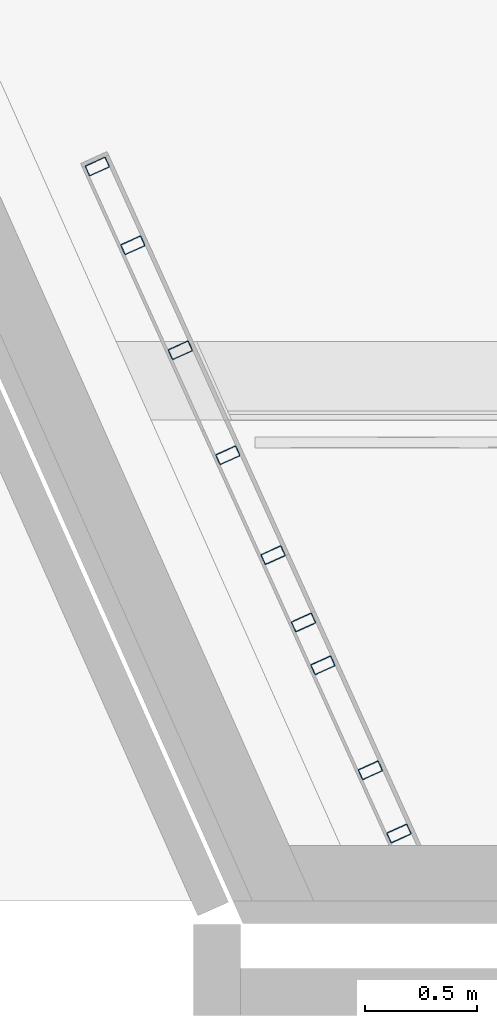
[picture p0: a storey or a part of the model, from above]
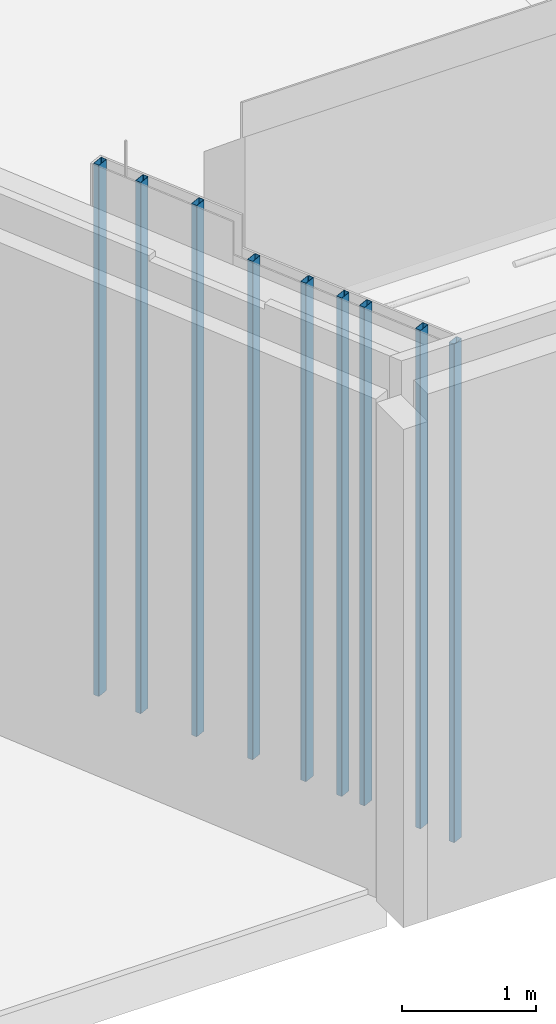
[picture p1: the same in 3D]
Properties of the parts of a building model (IFC2X3), part 1 of 2

# File
Description: ViewDefinition [CoordinationView_V2.0, QuantityTakeOffAddOnView]
File name: 10024017
Time: 2025-01-29T14:13:03+01:00
Written by: ODA SDAI 22.12
Made in: 23.0.11.19 - Exporter 23.0.11.19 - Alternate UI 23.0.11.19

# IfcProject, 10024017
LongName: CULTURA

# IfcSite, Default
RefLatitude: 52, 22, 22, 799999; RefLongitude: 4, 53, 41, 279999; RefElevation: 0 mm
Pset_ProductRequirements - Category: Project Information

# IfcBuilding
Pset_BuildingCommon - NumberOfStoreys: 4
Pset_ProductRequirements - Category: Project Information

# IfcBuildingStorey: Level:3.5mm bouwkundig (naam + hoogte) (4)
Pset_ProductRequirements - Category: Levels
Name | LongName | Elevation (mm) | Pset_AirSideSystemInformation, Name = Pset_ProductRequirements, Name
00 Begane grond | 00 Begane grond | 750 | 00 Begane grond o.k. vloer
01 1e verdieping | 01 1e verdieping | 4200 | 01 1e verdieping
02 2e verdieping | 02 2e verdieping | 9000 | 02 2e verdieping
03 3e verdieping | 03 3e verdieping | 12600 | 03 3e verdieping

# IfcSpace: BVO 2:5926632, 2
In: 00 Begane grond
Type - PredefinedType: USERDEFINED
LongName: BVO; InteriorOrExteriorSpace: INTERNAL; Group: BB. BVO
Pset_AirSideSystemInformation - Name: BVO
Pset_ProductRequirements - Name: BVO; Category: Areas
Pset_SpaceCommon - Reference: BVO 2; Category: Areas
BaseQuantities - NetFloorArea: 182.71 m2; Height: 3450 mm; GrossFloorArea: 182.71 m2; GrossVolume: 630.35 m3

# IfcSpace: BVO 4:6411099, 4
In: 01 1e verdieping
Type - PredefinedType: USERDEFINED
LongName: BVO; InteriorOrExteriorSpace: INTERNAL; Group: BB. BVO
Pset_AirSideSystemInformation - Name: BVO
Pset_ProductRequirements - Name: BVO; Category: Areas
Pset_SpaceCommon - Reference: BVO 4; Category: Areas
BaseQuantities - NetFloorArea: 341.625 m2; Height: 4800 mm; GrossFloorArea: 341.625 m2; GrossVolume: 1639.8 m3

# IfcSpace: BVO 5:6411158, 5
In: 02 2e verdieping
Type - PredefinedType: USERDEFINED
LongName: BVO; InteriorOrExteriorSpace: INTERNAL; Group: BB. BVO
Pset_AirSideSystemInformation - Name: BVO
Pset_ProductRequirements - Name: BVO; Category: Areas
Pset_SpaceCommon - Reference: BVO 5; Category: Areas
BaseQuantities - NetFloorArea: 78 m2; Height: 3600 mm; GrossFloorArea: 78 m2; GrossVolume: 280.8 m3

# IfcSpace: BVO 6:6413446, 6
In: 02 2e verdieping
Type - PredefinedType: USERDEFINED
LongName: BVO; InteriorOrExteriorSpace: INTERNAL; Group: BB. BVO
Pset_AirSideSystemInformation - Name: BVO
Pset_ProductRequirements - Name: BVO; Category: Areas
Pset_SpaceCommon - Reference: BVO 6; Category: Areas
BaseQuantities - NetFloorArea: 126 m2; Height: 3600 mm; GrossFloorArea: 126 m2; GrossVolume: 453.599 m3

# IfcSpace: Balkon 2.6:6415991, 2.6
In: 02 2e verdieping
LongName: Balkon; InteriorOrExteriorSpace: INTERNAL
Pset_AirSideSystemInformation - Name: Balkon
Pset_ProductRequirements - Name: Balkon; Category: Rooms
Pset_SpaceCommon - Reference: Balkon 2.6; Category: Rooms; FloorCovering: V2 Houten vloerafwerking
BaseQuantities - NetFloorArea: 319.853 m2; Height: 2438.4 mm; GrossFloorArea: 319.853 m2; GrossVolume: 779.93 m3

# IfcSpace: Multifunctionele zaal 1.4:6222861, 1.4
In: 01 1e verdieping
LongName: Multifunctionele zaal; InteriorOrExteriorSpace: INTERNAL
Pset_AirSideSystemInformation - Name: Multifunctionele zaal
Pset_ProductRequirements - Name: Multifunctionele zaal; Category: Rooms
Pset_SpaceCommon - Reference: Multifunctionele zaal 1.4; Category: Rooms; FloorCovering: V2 Houten vloerafwerking
BaseQuantities - NetFloorArea: 325.531 m2; Height: 2438.4 mm; GrossFloorArea: 325.531 m2; GrossVolume: 793.775 m3

# IfcSpace: Plateaulift 1.2:6222855, 1.2
In: 01 1e verdieping
LongName: Plateaulift; InteriorOrExteriorSpace: INTERNAL
Pset_AirSideSystemInformation - Name: Plateaulift
Pset_ProductRequirements - Name: Plateaulift; Category: Rooms
Pset_SpaceCommon - Reference: Plateaulift 1.2; Category: Rooms; FloorCovering: Geen vloerafwerking / vide; CeilingCovering: Geen plafondafwerking / vide
BaseQuantities - NetFloorArea: 1.27597 m2; Height: 2438.4 mm; GrossPerimeter: 4668.56 mm; GrossFloorArea: 1.27597 m2; GrossVolume: 3.11133 m3

# IfcSpace: Sluis 1.1:6222836, 1.1
In: 01 1e verdieping
LongName: Sluis; InteriorOrExteriorSpace: INTERNAL
Pset_AirSideSystemInformation - Name: Sluis
Pset_ProductRequirements - Name: Sluis; Category: Rooms
Pset_SpaceCommon - Reference: Sluis 1.1; Category: Rooms; FloorCovering: V1 Zachte vloerafwerking; CeilingCovering: P1 Systeemplafond
BaseQuantities - NetFloorArea: 3.37673 m2; Height: 2438.4 mm; GrossPerimeter: 7497.14 mm; GrossFloorArea: 3.37673 m2; GrossVolume: 8.23381 m3

# IfcSpace: Sluis 1.3:6222849, 1.3
In: 01 1e verdieping
LongName: Sluis; InteriorOrExteriorSpace: INTERNAL
Pset_AirSideSystemInformation - Name: Sluis
Pset_ProductRequirements - Name: Sluis; Category: Rooms
Pset_SpaceCommon - Reference: Sluis 1.3; Category: Rooms; FloorCovering: V1 Zachte vloerafwerking; CeilingCovering: P1 Systeemplafond
BaseQuantities - NetFloorArea: 3.03544 m2; Height: 2438.4 mm; GrossPerimeter: 8451.61 mm; GrossFloorArea: 3.03544 m2; GrossVolume: 7.40163 m3

# IfcSpace: Sluis 2.1:6356506, 2.1
In: 02 2e verdieping
LongName: Sluis; InteriorOrExteriorSpace: INTERNAL
Pset_AirSideSystemInformation - Name: Sluis
Pset_ProductRequirements - Name: Sluis; Category: Rooms
Pset_SpaceCommon - Reference: Sluis 2.1; Category: Rooms; FloorCovering: V1 Zachte vloerafwerking; CeilingCovering: P1 Systeemplafond
BaseQuantities - NetFloorArea: 3.37673 m2; Height: 2438.4 mm; GrossPerimeter: 7497.14 mm; GrossFloorArea: 3.37673 m2; GrossVolume: 8.23381 m3

# IfcSpace: Sluis 2.3:6356499, 2.3
In: 02 2e verdieping
LongName: Sluis; InteriorOrExteriorSpace: INTERNAL
Pset_AirSideSystemInformation - Name: Sluis
Pset_ProductRequirements - Name: Sluis; Category: Rooms
Pset_SpaceCommon - Reference: Sluis 2.3; Category: Rooms; FloorCovering: V1 Zachte vloerafwerking; CeilingCovering: P1 Systeemplafond
BaseQuantities - NetFloorArea: 3.0787 m2; Height: 2438.4 mm; GrossPerimeter: 8620.86 mm; GrossFloorArea: 3.0787 m2; GrossVolume: 7.5071 m3

# IfcSpace: Techniek 2.2:6356521, 2.2
In: 02 2e verdieping
LongName: Techniek; InteriorOrExteriorSpace: INTERNAL
Pset_AirSideSystemInformation - Name: Techniek
Pset_ProductRequirements - Name: Techniek; Category: Rooms
Pset_SpaceCommon - Reference: Techniek 2.2; Category: Rooms; FloorCovering: V3 Elastische vloerafwerking; CeilingCovering: P3 Sauswerk
BaseQuantities - NetFloorArea: 4.30041 m2; Height: 2438.4 mm; GrossFloorArea: 4.30041 m2; GrossVolume: 10.4861 m3

# IfcSpace: Theatertechniek 3.13:6422108, 3.13
In: 03 3e verdieping
LongName: Theatertechniek; InteriorOrExteriorSpace: INTERNAL
Pset_AirSideSystemInformation - Name: Theatertechniek
Pset_ProductRequirements - Name: Theatertechniek; Category: Rooms
Pset_SpaceCommon - Reference: Theatertechniek 3.13; Category: Rooms; CeilingCovering: P4 Systeemplafond
BaseQuantities - NetFloorArea: 102.625 m2; Height: 2438.4 mm; GrossFloorArea: 102.625 m2; GrossVolume: 250.241 m3

# IfcBuildingElementProxy: $9_APX_brandslanghaspel 30m - inbouw:$9_APX_brandslanghaspel 30m - inbouw (2)
In: 1.4
Type - Material: <Unnamed>
Type - Pset_ProductRequirements - Category: Generic Models
Pset_BuildingElementProxyCommon - Reference: $9_APX_brandslanghaspel 30m - inbouw:$9_APX_brandslanghaspel 30m - inbouw; sets with these values: 2
Name ($9_APX_brandslanghaspel 30m - inbouw:$9_APX_brandslanghaspel 30m - inbouw:...)
6395932
6396388

# IfcBuildingElementProxy: NLRS_53_GM_brandslanghaspel opbouw_ags:20 meter (13)
Type - Classification: 53.0 water; algemeen (Uniformat); Material: <Unnamed>
Type - Pset_ProductRequirements - Category: Generic Models
Pset_BuildingElementProxyCommon - Reference: NLRS_53_GM_brandslanghaspel opbouw_ags:20 meter; sets with these values: 2
Name (NLRS_53_GM_brandslanghaspel opbouw_ags:20 meter:...) | In
6379921 | 01 1e verdieping
6380212 | 2.1
6380439 | 02 2e verdieping
6380646 | 01 1e verdieping
6380734 | 02 2e verdieping
6390924 | 01 1e verdieping
6390974 | 02 2e verdieping
6391039 | 03 3e verdieping
6391112 | 03 3e verdieping
6391162 | 3.13
6391226 | 03 3e verdieping
6423973 | 01 1e verdieping
6449209 | 2.3

# IfcBuildingElementProxy: Storax-kooiladder-DLL-VM-K:GL-VM-K, Storax-kooiladder-DLL-VM-K:GL-VM-K:6451924
In: 02 2e verdieping
Type - Material: bcb_aluminium (43)
Type - Pset_ManufacturerTypeInformation - Manufacturer: Storax
Type - Pset_ProductRequirements - Category: Generic Models
Pset_BuildingElementProxyCommon - Reference: Storax-kooiladder-DLL-VM-K:GL-VM-K; sets with these values: 2
Pset_ProvisionForVoid - Width: 8 mm; Height: 70 mm; Depth: 70 mm

# IfcColumn: Kokerprofielen_ITX(c):K100/50/2.5 (39)
Type - PredefinedType: COLUMN; Classification: (28.a) (Uniformat); Material: Metal - Steel - 345 MPa
Type - Pset_ColumnCommon - IsExternal: no; LoadBearing: yes
Type - Pset_ProductRequirements - Category: Structural Columns
BaseQuantities - CrossSectionArea: 0.00070889 m2
Pset_ColumnCommon - Reference: Kokerprofielen_ITX(c):K100/50/2.5
Pset_QuantityTakeOff - Reference: Kokerprofielen_ITX(c):K100/50/2.5; sets with these values: 2
Name (Kokerprofielen_ITX(c):K100/50/2.5:...) | In | Length (mm) | OuterSurfaceArea (m2) | GrossVolume (m3) | NetVolume (m3)
6153715 | 01 1e verdieping | 4550 | 2.58041 | 0.00322545 | 0.00322534
6155034 | 01 1e verdieping | 4550 | 2.58041 | 0.00322545
6155050 | 01 1e verdieping | 4550 | 2.58041 | 0.00322545
6155062 | 01 1e verdieping | 4550 | 2.58041 | 0.00322545
6155076 | 01 1e verdieping | 4550 | 2.58041 | 0.00322545
6155090 | 01 1e verdieping | 4550 | 2.58041 | 0.00322545
6164741 | 01 1e verdieping | 4850 | 2.75055 | 0.00343811 | 0.00343799
6164741 | 02 2e verdieping | 3500 | 1.98493 | 0.00248111 | 0.00248103
6164755 | 01 1e verdieping | 4550 | 2.58041 | 0.00322545 | 0.00322534
6164765 | 01 1e verdieping | 4550 | 2.58041 | 0.00322545
6164779 | 01 1e verdieping | 4550 | 2.58041 | 0.00322545
6164791 | 01 1e verdieping | 4550 | 2.58041 | 0.00322545
6164801 | 01 1e verdieping | 4550 | 2.58041 | 0.00322545
6164815 | 01 1e verdieping | 4550 | 2.58041 | 0.00322545
6287158 | 02 2e verdieping | 3550 | 2.01329 | 0.00251656 | 0.00251647
6287159 | 02 2e verdieping | 3550 | 2.01329 | 0.00251656
6287160 | 02 2e verdieping | 3550 | 2.01329 | 0.00251656
6287161 | 02 2e verdieping | 3550 | 2.01329 | 0.00251656
6287162 | 02 2e verdieping | 1300 | 0.737261 | 0.000921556 | 0.000921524
6287163 | 02 2e verdieping | 1300 | 0.737261 | 0.000921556
6294994 | 02 2e verdieping | 1300 | 0.737261 | 0.000921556 | 0.000921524
6294995 | 02 2e verdieping | 1300 | 0.737261 | 0.000921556
6294996 | 02 2e verdieping | 1300 | 0.737261 | 0.000921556
6294997 | 02 2e verdieping | 3550 | 2.01329 | 0.00251656 | 0.00251647
6294998 | 02 2e verdieping | 3550 | 2.01329 | 0.00251656
6294999 | 02 2e verdieping | 3550 | 2.01329 | 0.00251656
6295000 | 02 2e verdieping | 3550 | 2.01329 | 0.00251656
6331567 | 01 1e verdieping | 4850 | 2.75055 | 0.00343811 | 0.00343799
6331567 | 02 2e verdieping | 3500 | 1.98493 | 0.00248111 | 0.00248103
6331577 | 01 1e verdieping | 4850 | 2.75055 | 0.00343811 | 0.00343799
6331577 | 02 2e verdieping | 3500 | 1.98493 | 0.00248111 | 0.00248103
6331587 | 01 1e verdieping | 4850 | 2.75055 | 0.00343811 | 0.00343799
6331587 | 02 2e verdieping | 3500 | 1.98493 | 0.00248111 | 0.00248103
6338354 | 01 1e verdieping | 4850 | 2.75055 | 0.00343811 | 0.00343799
6338354 | 02 2e verdieping | 3500 | 1.98493 | 0.00248111 | 0.00248103
6338366 | 01 1e verdieping | 4850 | 2.75055 | 0.00343811 | 0.00343799
6338366 | 02 2e verdieping | 3500 | 1.98493 | 0.00248111 | 0.00248103
6338687 | 01 1e verdieping | 4850 | 2.75055 | 0.00343811 | 0.00343799
6338687 | 02 2e verdieping | 3500 | 1.98493 | 0.00248111 | 0.00248103

# IfcCovering: Compound Ceiling:NLRS_45_CEI_ontwerpplafond 100mm_ags (3)
Type - PredefinedType: CEILING
Type - Pset_CoveringCommon - TotalThickness: 100 mm
Type - Pset_ElementShading - Roughness: 304.8 mm
Type - Pset_ProductRequirements - Category: Ceilings
Classification: 45.11 plafondafwerkingen; verlaagd, verlaagde plafonds (Uniformat); Material: NLRS_ontwerpmateriaal grijs 100 mm
Pset_CoveringCommon - Reference: Compound Ceiling:NLRS_45_CEI_ontwerpplafond 100mm_ags; sets with these values: 2
Name (Compound Ceiling:NLRS_45_CEI_ontwerpplafond 100mm_ags:...) | In | GrossCeilingArea (m2)
6311351 | 3.13 | 341.626
6344896 | 01 1e verdieping | 63.2539
6346580 | 01 1e verdieping | 31.6356

# IfcCurtainWall: Curtain Wall:NLRS_32_CWA_houten binnenkozijnen ts90_ags (24)
Type - Pset_CurtainWallCommon - IsExternal: no
Type - Pset_ProductRequirements - Category: Walls
Classification: 32.40 binnenwandopeningen; gevuld met puien, algemeen (verzamelniveau) (Uniformat)
Pset_CurtainWallCommon - Reference: Curtain Wall:NLRS_32_CWA_houten binnenkozijnen ts90_ags
Pset_QuantityTakeOff - Reference: Curtain Wall:NLRS_32_CWA_houten binnenkozijnen ts90_ags
Name (Curtain Wall:NLRS_32_CWA_houten binnenkozijnen ts90_ags:...) | In | Pset_ConcreteElementGeneral, FireRating = Pset_CurtainWallCommon, FireRating
6147847 | 01 1e verdieping | 30
6148407 | 01 1e verdieping | 30
6149483 | 01 1e verdieping | 30
6149900 | 01 1e verdieping | 60
6151805 | 01 1e verdieping | 30
6152954 | 01 1e verdieping | 30
6158346 | 01 1e verdieping | 30
6224134 | 01 1e verdieping | 30
6225151 | 02 2e verdieping | 30
6225855 | 02 2e verdieping | 30
6225909 | 02 2e verdieping | 30
6228164 | 02 2e verdieping | 60
6245156 | 01 1e verdieping | 0
6264043 | 02 2e verdieping | 30
6282615 | 01 1e verdieping | 0
6292872 | 02 2e verdieping | 30
6339797 | 01 1e verdieping | 0
6364564 | 01 1e verdieping | 30
6365035 | 02 2e verdieping | 30
6366062 | 02 2e verdieping | 30
6383929 | 03 3e verdieping | 60
6423692 | 02 2e verdieping | 30
6424522 | 01 1e verdieping | 0
6452049 | 02 2e verdieping

# IfcDoor: NLRS_31_DO_houten deur kiep boven_ags:deur dicht, NLRS_31_DO_houten deur kiep boven_ags:deur dicht:6260981
In: 01 1e verdieping
Type - ParameterTakesPrecedence: no; Sizeable: no; Classification: 31.31 buitenwandopeningen; gevuld met deuren, draaideuren (Uniformat); Material: NLRS_a_clashvolume, <Unnamed>
Type - Pset_DoorCommon - IsExternal: yes
Type - Pset_ProductRequirements - Category: Doors
OverallHeight: 613 mm; OverallWidth: 1731 mm; Classification: 32.40 binnenwandopeningen; gevuld met puien, algemeen (verzamelniveau) (Uniformat)
Pset_DoorCommon - Reference: NLRS_31_DO_houten deur kiep boven_ags:deur dicht
Pset_QuantityTakeOff - Reference: NLRS_31_DO_houten deur kiep boven_ags:deur dicht
BaseQuantities - Height: 613 mm; Width: 1731 mm; Area: 1.0611 m2

# IfcDoor: NLRS_31_DO_houten deur_ags:deur dicht (30)
Type - ParameterTakesPrecedence: no; Sizeable: no; Classification: 31.31 buitenwandopeningen; gevuld met deuren, draaideuren (Uniformat); Material: NLRS_a_clashvolume, <Unnamed>
Type - Pset_DoorCommon - IsExternal: yes
Type - Pset_ProductRequirements - Category: Doors
Classification: 32.40 binnenwandopeningen; gevuld met puien, algemeen (verzamelniveau) (Uniformat)
Pset_DoorCommon - Reference: NLRS_31_DO_houten deur_ags:deur dicht
Pset_QuantityTakeOff - Reference: NLRS_31_DO_houten deur_ags:deur dicht
Name (NLRS_31_DO_houten deur_ags:deur dicht:...) | In | OverallHeight (mm) = Height (mm) | OverallWidth (mm) = Width (mm) | Area (m2)
6147848 | 01 1e verdieping | 2103 | 1013 | 2.13034
6147853 | 01 1e verdieping | 2103 | 352.761 | 0.741856
6148408 | 01 1e verdieping | 2103 | 1086 | 2.28386
6149484 | 01 1e verdieping | 2103 | 906 | 1.90532
6149901 | 01 1e verdieping | 2103 | 886 | 1.86326
6151806 | 01 1e verdieping | 2320 | 865.5 | 2.00796
6151811 | 01 1e verdieping | 2320 | 865.5 | 2.00796
6152955 | 01 1e verdieping | 2103 | 906 | 1.90532
6158347 | 01 1e verdieping | 2103 | 931 | 1.95789
6224135 | 01 1e verdieping | 2103 | 807.995 | 1.69921
6224140 | 01 1e verdieping | 2103 | 808 | 1.69922
6225152 | 02 2e verdieping | 2103 | 918 | 1.93055
6225157 | 02 2e verdieping | 2103 | 447.761 | 0.941641
6225856 | 02 2e verdieping | 2103 | 906 | 1.90532
6225910 | 02 2e verdieping | 2103 | 931 | 1.95789
6228165 | 02 2e verdieping | 2103 | 886 | 1.86326
6264044 | 02 2e verdieping | 2103 | 886 | 1.86326
6282616 | 01 1e verdieping | 2103 | 800.323 | 1.68308
6282621 | 01 1e verdieping | 2103 | 800.323 | 1.68308
6292873 | 02 2e verdieping | 2103 | 886 | 1.86326
6339798 | 01 1e verdieping | 2103 | 800.323 | 1.68308
6339803 | 01 1e verdieping | 2103 | 800.323 | 1.68308
6365036 | 02 2e verdieping | 2103 | 598.65 | 1.25896
6365041 | 02 2e verdieping | 2103 | 1013 | 2.13034
6366063 | 02 2e verdieping | 2103 | 807.995 | 1.69921
6366068 | 02 2e verdieping | 2103 | 808 | 1.69922
6383930 | 03 3e verdieping | 2103 | 806 | 1.69502
6423693 | 02 2e verdieping | 2103 | 906 | 1.90532
6424523 | 01 1e verdieping | 2103 | 933 | 1.9621
6424779 | 01 1e verdieping | 2103 | 783 | 1.64665

# IfcDoor: NLRS_31_DO_houten deur_ags:deur met maximaal glas (2)
In: 01 1e verdieping
Type - ParameterTakesPrecedence: no; Sizeable: no; Classification: 31.31 buitenwandopeningen; gevuld met deuren, draaideuren (Uniformat); Material: NLRS_a_clashvolume, Glas, <Unnamed>
Type - Pset_DoorCommon - IsExternal: yes
Type - Pset_ProductRequirements - Category: Doors
OverallHeight: 2103 mm; Classification: 32.40 binnenwandopeningen; gevuld met puien, algemeen (verzamelniveau) (Uniformat)
Pset_DoorCommon - Reference: NLRS_31_DO_houten deur_ags:deur met maximaal glas
Pset_QuantityTakeOff - Reference: NLRS_31_DO_houten deur_ags:deur met maximaal glas
BaseQuantities - Height: 2103 mm
Name (NLRS_31_DO_houten deur_ags:deur met maximaal glas:...) | OverallWidth (mm) = Width (mm) | Area (m2)
6364565 | 703 | 1.47841
6364570 | 1013 | 2.13034

# IfcFurnishingElement: Chair-Hussey-Quattro-Art_Series-Linear-3D-Metric:Chair-Hussey-Quattro-Art_Series-Linear-3D-Metric, Chair-Hussey-Quattro-Art_Series-Linear-3D-Metric:Chair-Hussey-Quattro-Art_Series-Linear-3D-Metric:6213181
In: 01 1e verdieping
Type - Classification: E2010500 (Uniformat); Material: Hussey - Fabric - Culp Contract - Dillon - Cordovan (2), Hussey - Wood - Grasswood - Natural Finish (6), Hussey - Paint - Titanium (26), <Unnamed> (2)
Type - Pset_FurnitureTypeCommon - Description: Quattro Art Series
Type - Pset_ManufacturerTypeInformation - Manufacturer: Hussey Seating Company
Type - Pset_ProductRequirements - Category: Furniture
Pset_QuantityTakeOff - Reference: Chair-Hussey-Quattro-Art_Series-Linear-3D-Metric:Chair-Hussey-Quattro-Art_Series-Linear-3D-Metric

# IfcFurnishingElement: Chair-Hussey-Quattro-Classic-3D:Chair-Hussey-Quattro-Classic-3D, Chair-Hussey-Quattro-Classic-3D:Chair-Hussey-Quattro-Classic-3D:6213133
In: 01 1e verdieping
Type - Classification: E2010500 (Uniformat); Material: <Unnamed> (27), Hussey - Seat Pad - Generic (2)
Type - Pset_FurnitureTypeCommon - Description: Quattro Collection
Type - Pset_ManufacturerTypeInformation - Manufacturer: Hussey Seating Company
Type - Pset_ProductRequirements - Category: Furniture
Pset_QuantityTakeOff - Reference: Chair-Hussey-Quattro-Classic-3D:Chair-Hussey-Quattro-Classic-3D

# IfcMember: Rectangular Mullion:NLRS_32_CWM_hout 114x67_ags (85)
Type - PredefinedType: MULLION; Material: <Unnamed>
Type - Pset_MemberCommon - IsExternal: no
Type - Pset_ProductRequirements - Category: Curtain Wall Mullions
Classification: 32.40 binnenwandopeningen; gevuld met puien, algemeen (verzamelniveau) (Uniformat)
Pset_MemberCommon - Reference: Rectangular Mullion:NLRS_32_CWM_hout 114x67_ags
Pset_QuantityTakeOff - Reference: Rectangular Mullion:NLRS_32_CWM_hout 114x67_ags
Name (Rectangular Mullion:NLRS_32_CWM_hout 114x67_ags:...) | In | Span (mm) = Length (mm) | CrossSectionArea (m2) | NetVolume (m3) | NetSurfaceArea (m2)
6147849 | 01 1e verdieping | 419.761 | 0.0836147 | 0.00320613 | 0.159591
6147850 | 01 1e verdieping | 2103 | 0.388281 | 0.0160627 | 0.776562
6147851 | 01 1e verdieping | 2103 | 0.388281 | 0.0160627 | 0.776562
6147854 | 01 1e verdieping | 1080 | 0.203118 | 0.00824904 | 0.398598
6148410 | 01 1e verdieping | 1086 | 0.204204 | 0.00829487 | 0.408408
6148412 | 01 1e verdieping | 2170 | 0.400408 | 0.0165745 | 0.800816
6148413 | 01 1e verdieping | 2170 | 0.400408 | 0.0165745 | 0.800816
6149485 | 01 1e verdieping | 906 | 0.171624 | 0.00692003 | 0.343248
6149486 | 01 1e verdieping | 2170 | 0.400408 | 0.0165745 | 0.800816
6149487 | 01 1e verdieping | 2170 | 0.400408 | 0.0165745 | 0.800816
6149902 | 01 1e verdieping | 886 | 0.168004 | 0.00676727 | 0.336008
6149903 | 01 1e verdieping | 2170 | 0.400408 | 0.0165745 | 0.800816
6149904 | 01 1e verdieping | 2170 | 0.400408 | 0.0165745 | 0.800816
6151807 | 01 1e verdieping | 865.5 | 0.164294 | 0.00661069 | 0.320949
6151808 | 01 1e verdieping | 2320 | 0.427558 | 0.0177202 | 0.847478
6151809 | 01 1e verdieping | 613 | 0.118591 | 0.00468209 | 0.229544
6151812 | 01 1e verdieping | 932.5 | 0.17642 | 0.00712243 | 0.345203
6260990 | 01 1e verdieping | 680 | 0.130718 | 0.00519384 | 0.253798
6260991 | 01 1e verdieping | 2320 | 0.427558 | 0.0177202 | 0.847478
6152956 | 01 1e verdieping | 906 | 0.171624 | 0.00692003 | 0.343248
6152957 | 01 1e verdieping | 2170 | 0.400408 | 0.0165745 | 0.800816
6152958 | 01 1e verdieping | 2170 | 0.400408 | 0.0165745 | 0.800816
6158348 | 01 1e verdieping | 931 | 0.176149 | 0.00711098 | 0.352298
6158349 | 01 1e verdieping | 2170 | 0.400408 | 0.0165745 | 0.800816
6158350 | 01 1e verdieping | 2170 | 0.400408 | 0.0165745 | 0.800816
6224136 | 01 1e verdieping | 875 | 0.166013 | 0.00668325 | 0.324388
6224137 | 01 1e verdieping | 2103 | 0.388281 | 0.0160627 | 0.776562
6224138 | 01 1e verdieping | 2103 | 0.388281 | 0.0160627 | 0.776562
6224141 | 01 1e verdieping | 874.995 | 0.166012 | 0.00668321 | 0.324386
6225153 | 02 2e verdieping | 514.761 | 0.10081 | 0.00393174 | 0.193981
6225154 | 02 2e verdieping | 2103 | 0.388281 | 0.0160627 | 0.776562
6225155 | 02 2e verdieping | 2103 | 0.388281 | 0.0160627 | 0.776562
6225158 | 02 2e verdieping | 985 | 0.185923 | 0.00752343 | 0.364208
6225857 | 02 2e verdieping | 906 | 0.171624 | 0.00692003 | 0.343248
6225858 | 02 2e verdieping | 2170 | 0.400408 | 0.0165745 | 0.800816
6225859 | 02 2e verdieping | 2170 | 0.400408 | 0.0165745 | 0.800816
6225911 | 02 2e verdieping | 931 | 0.176149 | 0.00711098 | 0.352298
6225912 | 02 2e verdieping | 2170 | 0.400408 | 0.0165745 | 0.800816
6225913 | 02 2e verdieping | 2170 | 0.400408 | 0.0165745 | 0.800816
6228166 | 02 2e verdieping | 886 | 0.168004 | 0.00676727 | 0.336008
6228167 | 02 2e verdieping | 2170 | 0.400408 | 0.0165745 | 0.800816
6228168 | 02 2e verdieping | 2170 | 0.400408 | 0.0165745 | 0.800816
6245158 | 01 1e verdieping | 886 | 0.168004 | 0.00676727 | 0.336008
6245159 | 01 1e verdieping | 2170 | 0.400408 | 0.0165745 | 0.800816
6245160 | 01 1e verdieping | 2170 | 0.400408 | 0.0165745 | 0.800816
6264045 | 02 2e verdieping | 886 | 0.168004 | 0.00676727 | 0.336008
6264046 | 02 2e verdieping | 2170 | 0.400408 | 0.0165745 | 0.800816
6264047 | 02 2e verdieping | 2170 | 0.400408 | 0.0165745 | 0.800816
6282617 | 01 1e verdieping | 867.323 | 0.164623 | 0.00662461 | 0.321609
6282618 | 01 1e verdieping | 2103 | 0.388281 | 0.0160627 | 0.776562
6282619 | 01 1e verdieping | 2103 | 0.388281 | 0.0160627 | 0.776562
6282622 | 01 1e verdieping | 867.323 | 0.164623 | 0.00662461 | 0.321609
6292874 | 02 2e verdieping | 886 | 0.168004 | 0.00676727 | 0.336008
6292875 | 02 2e verdieping | 2170 | 0.400408 | 0.0165745 | 0.800816
6292876 | 02 2e verdieping | 2170 | 0.400408 | 0.0165745 | 0.800816
6339799 | 01 1e verdieping | 867.323 | 0.164623 | 0.00662461 | 0.321609
6339800 | 01 1e verdieping | 2103 | 0.388281 | 0.0160627 | 0.776562
6339801 | 01 1e verdieping | 2103 | 0.388281 | 0.0160627 | 0.776562
6339804 | 01 1e verdieping | 867.323 | 0.164623 | 0.00662461 | 0.321609
6364566 | 01 1e verdieping | 1080 | 0.203118 | 0.00824904 | 0.398598
6364567 | 01 1e verdieping | 2103 | 0.388281 | 0.0160627 | 0.776562
6364568 | 01 1e verdieping | 2103 | 0.388281 | 0.0160627 | 0.776562
6364571 | 01 1e verdieping | 770 | 0.147008 | 0.00588126 | 0.286378
6365037 | 02 2e verdieping | 1080 | 0.203118 | 0.00824904 | 0.398598
6365038 | 02 2e verdieping | 2103 | 0.388281 | 0.0160627 | 0.776562
6365039 | 02 2e verdieping | 2103 | 0.388281 | 0.0160627 | 0.776562
6365042 | 02 2e verdieping | 665.65 | 0.128121 | 0.00508423 | 0.248603
6366064 | 02 2e verdieping | 875 | 0.166013 | 0.00668325 | 0.324388
6366065 | 02 2e verdieping | 2103 | 0.388281 | 0.0160627 | 0.776562
6366066 | 02 2e verdieping | 2103 | 0.388281 | 0.0160627 | 0.776562
6366069 | 02 2e verdieping | 874.995 | 0.166012 | 0.00668321 | 0.324386
6383931 | 03 3e verdieping | 806 | 0.153524 | 0.00615623 | 0.307048
6383932 | 03 3e verdieping | 2170 | 0.400408 | 0.0165745 | 0.800816
6383933 | 03 3e verdieping | 2170 | 0.400408 | 0.0165745 | 0.800816
6423694 | 02 2e verdieping | 906 | 0.171624 | 0.00692003 | 0.343248
6423695 | 02 2e verdieping | 2170 | 0.400408 | 0.0165745 | 0.800816
6423696 | 02 2e verdieping | 2170 | 0.400408 | 0.0165745 | 0.800816
6424524 | 01 1e verdieping | 850 | 0.161488 | 0.0064923 | 0.315338
6424525 | 01 1e verdieping | 2103 | 0.388281 | 0.0160627 | 0.776562
6424526 | 01 1e verdieping | 2103 | 0.388281 | 0.0160627 | 0.776562
6424785 | 01 1e verdieping | 1000 | 0.188638 | 0.007638 | 0.369638
6452091 | 02 2e verdieping | 416 | 0.082934 | 0.00317741 | 0.165868
6452092 | 02 2e verdieping | 416 | 0.082934 | 0.00317741 | 0.165868
6452093 | 02 2e verdieping | 550 | 0.107188 | 0.0042009 | 0.214376
6452094 | 02 2e verdieping | 550 | 0.107188 | 0.0042009 | 0.214376

# IfcOpeningElement: Opening (65)
Pset_OpeningElementCommon - sets with these values: 2
Name | In | Classification | Reference | Category | Depth (mm) | Height (mm) | Width (mm)
Basic Wall:NLRS_22_WA_kalkzandsteen 150mm_ags:6136175 | 01 1e verdieping | 22.11 binnenwanden; niet constructief, massieve wanden (Uniformat) | Constructie voids:Constructie voids | Walls
Basic Wall:NLRS_21_WA_beton 250mm_ags:6137919 | 01 1e verdieping | 21.11 buitenwanden; niet constructief, massieve wanden (Uniformat) | Basic Wall:NLRS_21_WA_beton 250mm_ags | Walls: Rectangular Straight Wall Opening | 250 | 1040 | 2220
Basic Wall:NLRS_21_WA_beton 250mm_ags:6138007 | 01 1e verdieping | 21.11 buitenwanden; niet constructief, massieve wanden (Uniformat) | Basic Wall:NLRS_21_WA_beton 250mm_ags | Walls: Rectangular Straight Wall Opening | 250 | 1840 | 2220
Basic Wall:NLRS_21_WA_beton 250mm_ags:6138079 | 01 1e verdieping | 21.11 buitenwanden; niet constructief, massieve wanden (Uniformat) | Basic Wall:NLRS_21_WA_beton 250mm_ags | Walls: Rectangular Straight Wall Opening | 250 | 1865 | 3050
Basic Wall:NLRS_22_WA_kalkzandsteen 150mm_ags:6138243 | 01 1e verdieping | 22.11 binnenwanden; niet constructief, massieve wanden (Uniformat) | Basic Wall:NLRS_22_WA_kalkzandsteen 150mm_ags | Walls: Rectangular Straight Wall Opening | 150 | 1040 | 2220
Basic Wall:NLRS_22_WA_kalkzandsteen 150mm_ags:6138328 | 01 1e verdieping | 22.11 binnenwanden; niet constructief, massieve wanden (Uniformat) | Basic Wall:NLRS_22_WA_kalkzandsteen 150mm_ags | Walls: Rectangular Straight Wall Opening | 150 | 1840 | 2170
Basic Wall:NLRS_22_WA_kalkzandsteen 150mm_ags:6138469 | 01 1e verdieping | 22.11 binnenwanden; niet constructief, massieve wanden (Uniformat) | Basic Wall:NLRS_22_WA_kalkzandsteen 150mm_ags | Walls: Rectangular Straight Wall Opening | 150 | 1865 | 3050
Basic Wall:NLRS_22_WA_kalkzandsteen 150mm_ags:6138469 | 01 1e verdieping | 22.11 binnenwanden; niet constructief, massieve wanden (Uniformat) | Curtain Wall:NLRS_32_CWA_houten binnenkozijnen ts90_ags | Walls | 454.8 | 3000 | 1865
2 x Basic Wall:NLRS_22_WA_kalkzandsteen 150mm_ags:6138796 | 01 1e verdieping | 22.11 binnenwanden; niet constructief, massieve wanden (Uniformat) | Basic Wall:NLRS_22_WA_kalkzandsteen 150mm_ags | Walls: Rectangular Straight Wall Opening | 150 | 1499.76 | 2220
Basic Wall:NLRS_22_WA_kalkzandsteen 150mm_ags:6138796 | 01 1e verdieping | 22.11 binnenwanden; niet constructief, massieve wanden (Uniformat) | Curtain Wall:NLRS_32_CWA_houten binnenkozijnen ts90_ags | Walls | 454.8 | 1499.76 | 2170
Basic Wall:NLRS_22_WA_kalkzandsteen 150mm_ags:6138796 | 01 1e verdieping | 22.11 binnenwanden; niet constructief, massieve wanden (Uniformat) | Constructie voids:Constructie voids | Walls
Basic Wall:NLRS_21_WA_beton 250mm_ags:6140967 | 01 1e verdieping | 21.11 buitenwanden; niet constructief, massieve wanden (Uniformat) | Basic Wall:NLRS_21_WA_beton 250mm_ags | Walls: Rectangular Straight Wall Opening | 250 | 1065 | 2220
2 x Basic Wall:NLRS_22_WA_kalkzandsteen 150mm_ags:6142320 | 01 1e verdieping | 22.11 binnenwanden; niet constructief, massieve wanden (Uniformat) | Basic Wall:NLRS_22_WA_kalkzandsteen 150mm_ags | Walls: Rectangular Straight Wall Opening | 150 | 1020 | 2220
Basic Wall:NLRS_22_WA_kalkzandsteen 150mm_ags:6142320 | 01 1e verdieping | 22.11 binnenwanden; niet constructief, massieve wanden (Uniformat) | Curtain Wall:NLRS_32_CWA_houten binnenkozijnen ts90_ags | Walls | 454.8 | 1020 | 2170
2 x Basic Wall:NLRS_22_WA_kalkzandsteen 150mm_ags:6142474 | 01 1e verdieping | 22.11 binnenwanden; niet constructief, massieve wanden (Uniformat) | Basic Wall:NLRS_22_WA_kalkzandsteen 150mm_ags | Walls: Rectangular Straight Wall Opening | 150 | 1065 | 2220
Basic Wall:NLRS_21_WA_beton 250mm_ags:6143536 | 02 2e verdieping | 21.11 buitenwanden; niet constructief, massieve wanden (Uniformat) | Basic Wall:NLRS_21_WA_beton 250mm_ags | Walls: Rectangular Straight Wall Opening | 250 | 940 | 2220
Basic Wall:NLRS_21_WA_beton 250mm_ags:6143536 | 03 3e verdieping | 21.11 buitenwanden; niet constructief, massieve wanden (Uniformat) | Basic Wall:NLRS_21_WA_beton 250mm_ags | Walls: Rectangular Straight Wall Opening | 250 | 940 | 2220
Basic Wall:NLRS_21_WA_beton 250mm_ags:6143537 | 02 2e verdieping | 21.11 buitenwanden; niet constructief, massieve wanden (Uniformat) | Basic Wall:NLRS_21_WA_beton 250mm_ags | Walls: Rectangular Straight Wall Opening | 250 | 1030 | 2220
Basic Wall:NLRS_21_WA_beton 250mm_ags:6143539 | 02 2e verdieping | 21.11 buitenwanden; niet constructief, massieve wanden (Uniformat) | Basic Wall:NLRS_21_WA_beton 250mm_ags | Walls: Rectangular Straight Wall Opening | 250 | 1065 | 2220
Basic Wall:NLRS_21_WA_beton 250mm_ags:6143544 | 02 2e verdieping | 21.11 buitenwanden; niet constructief, massieve wanden (Uniformat) | Basic Wall:NLRS_21_WA_beton 250mm_ags | Walls: Rectangular Straight Wall Opening | 250 | 1065 | 2220
Basic Wall:NLRS_22_WA_kalkzandsteen 150mm_ags:6144485 | 02 2e verdieping | 22.11 binnenwanden; niet constructief, massieve wanden (Uniformat) | Basic Wall:NLRS_22_WA_kalkzandsteen 150mm_ags | Walls: Rectangular Straight Wall Opening | 150 | 940 | 2220
Basic Wall:NLRS_22_WA_kalkzandsteen 150mm_ags:6144485 | 03 3e verdieping | 22.11 binnenwanden; niet constructief, massieve wanden (Uniformat) | Basic Wall:NLRS_22_WA_kalkzandsteen 150mm_ags | Walls: Rectangular Straight Wall Opening | 150 | 940 | 2220
Basic Wall:NLRS_22_WA_kalkzandsteen 150mm_ags:6144485 | 03 3e verdieping | 22.11 binnenwanden; niet constructief, massieve wanden (Uniformat) | Curtain Wall:NLRS_32_CWA_houten binnenkozijnen ts90_ags | Walls | 454.8 | 940 | 2170
Basic Wall:NLRS_22_WA_kalkzandsteen 150mm_ags:6144486 | 02 2e verdieping | 22.11 binnenwanden; niet constructief, massieve wanden (Uniformat) | Basic Wall:NLRS_22_WA_kalkzandsteen 150mm_ags | Walls: Rectangular Straight Wall Opening | 150 | 1030 | 2220
Basic Wall:NLRS_22_WA_kalkzandsteen 150mm_ags:6144489 | 02 2e verdieping | 22.11 binnenwanden; niet constructief, massieve wanden (Uniformat) | Basic Wall:NLRS_22_WA_kalkzandsteen 150mm_ags | Walls: Rectangular Straight Wall Opening | 150 | 1065 | 2220
Basic Wall:NLRS_22_WA_kalkzandsteen 150mm_ags:6144490 | 02 2e verdieping | 22.11 binnenwanden; niet constructief, massieve wanden (Uniformat) | Curtain Wall:NLRS_32_CWA_houten binnenkozijnen ts90_ags | Walls | 454.8 | 1499.76 | 2170
Basic Wall:NLRS_22_WA_kalkzandsteen 150mm_ags:6144492 | 02 2e verdieping | 22.11 binnenwanden; niet constructief, massieve wanden (Uniformat) | Curtain Wall:NLRS_32_CWA_houten binnenkozijnen ts90_ags | Walls | 454.8 | 1020 | 2170
Basic Wall:NLRS_22_WA_kalkzandsteen 150mm_ags:6144494 | 02 2e verdieping | 22.11 binnenwanden; niet constructief, massieve wanden (Uniformat) | Curtain Wall:NLRS_32_CWA_houten binnenkozijnen ts90_ags | Walls | 454.8 | 1065 | 2170
Basic Wall:NLRS_22_WA_ms-wand mdf gips iso gips gips 125mm 25-75-25_ags:6147858 | 01 1e verdieping | 22.13 binnenwanden; niet constructief, systeemwanden; vast (Uniformat) | Curtain Wall:NLRS_32_CWA_houten binnenkozijnen ts90_ags | Walls | 429.8 | 2170 | 1220
Basic Wall:NLRS_22_WA_ms-wand mdf gips iso gips gips 125mm 25-75-25_ags:6149482 | 01 1e verdieping | 22.13 binnenwanden; niet constructief, systeemwanden; vast (Uniformat) | Curtain Wall:NLRS_32_CWA_houten binnenkozijnen ts90_ags | Walls | 429.8 | 2170 | 1040
Basic Wall:NLRS_21_WA_isolatie 80mm_ags:6156949 | 02 2e verdieping | 21.10 buitenwanden; niet constructief, algemeen (verzamelniveau) (Uniformat) | Basic Wall:NLRS_21_WA_isolatie 80mm_ags | Walls: Rectangular Straight Wall Opening | 80 | 940 | 2220
Basic Wall:NLRS_21_WA_isolatie 80mm_ags:6156949 | 03 3e verdieping | 21.10 buitenwanden; niet constructief, algemeen (verzamelniveau) (Uniformat) | Basic Wall:NLRS_21_WA_isolatie 80mm_ags | Walls: Rectangular Straight Wall Opening | 80 | 940 | 2220
Basic Wall:NLRS_21_WA_isolatie 80mm_ags:6157103 | 01 1e verdieping | 21.10 buitenwanden; niet constructief, algemeen (verzamelniveau) (Uniformat) | Basic Wall:NLRS_21_WA_isolatie 80mm_ags | Walls: Rectangular Straight Wall Opening | 80 | 1040 | 2220
Basic Wall:NLRS_21_WA_isolatie 80mm_ags:6157103 | 01 1e verdieping | 21.10 buitenwanden; niet constructief, algemeen (verzamelniveau) (Uniformat) | Basic Wall:NLRS_21_WA_isolatie 80mm_ags | Walls: Rectangular Straight Wall Opening | 80 | 1030 | 2220
Basic Wall:NLRS_21_WA_isolatie 80mm_ags:6157103 | 02 2e verdieping | 21.10 buitenwanden; niet constructief, algemeen (verzamelniveau) (Uniformat) | Basic Wall:NLRS_21_WA_isolatie 80mm_ags | Walls: Rectangular Straight Wall Opening | 80 | 1030 | 2220
Basic Wall:NLRS_21_WA_isolatie 80mm_ags:6157210 | 01 1e verdieping | 21.10 buitenwanden; niet constructief, algemeen (verzamelniveau) (Uniformat) | Basic Wall:NLRS_21_WA_isolatie 80mm_ags | Walls: Rectangular Straight Wall Opening | 80 | 1840 | 2220
Basic Wall:NLRS_21_WA_isolatie 80mm_ags:6157323 | 01 1e verdieping | 21.10 buitenwanden; niet constructief, algemeen (verzamelniveau) (Uniformat) | Basic Wall:NLRS_21_WA_isolatie 80mm_ags | Walls: Rectangular Straight Wall Opening | 80 | 1865 | 3050
Basic Wall:NLRS_21_WA_isolatie 80mm_ags:6157323 | 01 1e verdieping | 21.10 buitenwanden; niet constructief, algemeen (verzamelniveau) (Uniformat) | Basic Wall:NLRS_21_WA_isolatie 80mm_ags | Walls: Rectangular Straight Wall Opening | 80 | 1065 | 2220
Basic Wall:NLRS_21_WA_isolatie 80mm_ags:6157323 | 02 2e verdieping | 21.10 buitenwanden; niet constructief, algemeen (verzamelniveau) (Uniformat) | Basic Wall:NLRS_21_WA_isolatie 80mm_ags | Walls: Rectangular Straight Wall Opening | 80 | 1065 | 2220
Basic Wall:NLRS_21_WA_isolatie 80mm_ags:6157323 | 02 2e verdieping | 21.10 buitenwanden; niet constructief, algemeen (verzamelniveau) (Uniformat) | Basic Wall:NLRS_21_WA_isolatie 80mm_ags | Walls: Rectangular Straight Wall Opening | 80 | 1.38167 | 2438.4
2 x Basic Wall:NLRS_21_WA_isolatie 80mm_ags:6157533 | 01 1e verdieping | 21.10 buitenwanden; niet constructief, algemeen (verzamelniveau) (Uniformat) | Basic Wall:NLRS_21_WA_isolatie 80mm_ags | Walls: Rectangular Straight Wall Opening | 80 | 1020 | 2220
Basic Wall:NLRS_21_WA_isolatie 80mm_ags:6157533 | 02 2e verdieping | 21.10 buitenwanden; niet constructief, algemeen (verzamelniveau) (Uniformat) | Basic Wall:NLRS_21_WA_isolatie 80mm_ags | Walls: Rectangular Straight Wall Opening | 80 | 1020 | 2220
2 x Basic Wall:NLRS_21_WA_isolatie 80mm_ags:6157612 | 01 1e verdieping | 21.10 buitenwanden; niet constructief, algemeen (verzamelniveau) (Uniformat) | Basic Wall:NLRS_21_WA_isolatie 80mm_ags | Walls: Rectangular Straight Wall Opening | 80 | 1065 | 2220
Basic Wall:NLRS_21_WA_isolatie 80mm_ags:6157612 | 02 2e verdieping | 21.10 buitenwanden; niet constructief, algemeen (verzamelniveau) (Uniformat) | Basic Wall:NLRS_21_WA_isolatie 80mm_ags | Walls: Rectangular Straight Wall Opening | 80 | 1065 | 2220
2 x Basic Wall:NLRS_21_WA_isolatie 80mm_ags:6157723 | 01 1e verdieping | 21.10 buitenwanden; niet constructief, algemeen (verzamelniveau) (Uniformat) | Basic Wall:NLRS_21_WA_isolatie 80mm_ags | Walls: Rectangular Straight Wall Opening | 80 | 1499.76 | 2220
Basic Wall:NLRS_21_WA_isolatie 80mm_ags:6157723 | 01 1e verdieping | 21.10 buitenwanden; niet constructief, algemeen (verzamelniveau) (Uniformat) | Constructie voids:Constructie voids | Walls
Basic Wall:NLRS_21_WA_isolatie 80mm_ags:6157723 | 02 2e verdieping | 21.10 buitenwanden; niet constructief, algemeen (verzamelniveau) (Uniformat) | Basic Wall:NLRS_21_WA_isolatie 80mm_ags | Walls: Rectangular Straight Wall Opening | 80 | 1499.76 | 2220
Basic Wall:NLRS_21_WA_isolatie 80mm_ags:6157723 | 02 2e verdieping | 21.10 buitenwanden; niet constructief, algemeen (verzamelniveau) (Uniformat) | Constructie voids:Constructie voids | Walls
Floor:NLRS_43_FL_parketvloer zaal 97mm_ags:6222776:2 | 01 1e verdieping | 43.20 vloerafwerkingen; niet verhoogd, algemeen (verzamelniveau) (Uniformat) | Floor:NLRS_43_FL_parketvloer zaal 97mm_ags | Floors | 97 | BaseQuantities - Area: 113.871 m2
Basic Wall:NLRS_22_WA_ms-wand mdf gips iso gips gips 125mm 25-75-25_ags:6225281 | 02 2e verdieping | 22.13 binnenwanden; niet constructief, systeemwanden; vast (Uniformat) | Curtain Wall:NLRS_32_CWA_houten binnenkozijnen ts90_ags | Walls | 429.8 | 2170 | 1040
Basic Wall:NLRS_22_WA_ms-wand mdf gips iso gips gips 125mm 25-75-25_ags:6225749 | 02 2e verdieping | 22.13 binnenwanden; niet constructief, systeemwanden; vast (Uniformat) | Curtain Wall:NLRS_32_CWA_houten binnenkozijnen ts90_ags | Walls | 429.8 | 2170 | 1040
Basic Wall:NLRS_22_WA_ms-wand gips iso gips 125mm 25-75-25_ags:6227912 | 02 2e verdieping | 22.13 binnenwanden; niet constructief, systeemwanden; vast (Uniformat) | Curtain Wall:NLRS_32_CWA_houten binnenkozijnen ts90_ags | Walls | 429.8 | 550 | 550
Basic Wall:NLRS_22_WA_ms-wand gips iso gips 125mm 25-75-25_ags:6244194 | 01 1e verdieping | 22.13 binnenwanden; niet constructief, systeemwanden; vast (Uniformat) | Curtain Wall:NLRS_32_CWA_houten binnenkozijnen ts90_ags | Walls | 429.8 | 2170 | 1020
Basic Wall:NLRS_22_WA_ms-wand mdf gips iso 125mm 25-100_ags:6256860 | 01 1e verdieping | 22.13 binnenwanden; niet constructief, systeemwanden; vast (Uniformat) | Curtain Wall:NLRS_32_CWA_houten binnenkozijnen ts90_ags | Walls | 429.8 | 2170 | 1020
Basic Wall:NLRS_22_WA_akoestische voorzetwand 115mm 39-1-75_ags:6256955 | 01 1e verdieping | 22.13 binnenwanden; niet constructief, systeemwanden; vast (Uniformat) | Curtain Wall:NLRS_32_CWA_houten binnenkozijnen ts90_ags | Walls | 419.8 | 2170 | 1020
Basic Wall:NLRS_22_WA_ms-wand mdfi gips iso 200mm 25-175_ags:6285388 | 02 2e verdieping | 22.13 binnenwanden; niet constructief, systeemwanden; vast (Uniformat) | Basic Wall:NLRS_22_WA_ms-wand mdfi gips iso 200mm 25-175_ags | Walls: Rectangular Straight Wall Opening | 200 | 550 | 550
Floor:NLRS_43_FL_roostervloer 30mm_ags:6380821:2 | 03 3e verdieping | 23.10 vloeren; niet constructief, algemeen (verzamelniveau) (Uniformat) | Floor:NLRS_43_FL_roostervloer 30mm_ags | Floors | 30 | BaseQuantities - Area: 189.52 m2
Floor:NLRS_43_FL_roostervloer 30mm_ags:6380821:3 | 03 3e verdieping | 23.10 vloeren; niet constructief, algemeen (verzamelniveau) (Uniformat) | Floor:NLRS_43_FL_roostervloer 30mm_ags | Floors | 30 | BaseQuantities - Area: 49.7444 m2
Basic Wall:NLRS_22_WA_ms-wand gips iso gips 125mm 25-75-25_ags:6424319 | 01 1e verdieping | 22.13 binnenwanden; niet constructief, systeemwanden; vast (Uniformat) | Curtain Wall:NLRS_32_CWA_houten binnenkozijnen ts90_ags | Walls | 429.8 | 2170 | 1850

# IfcOpeningElement: Recess, Basic Wall:NLRS_21_WA_beton 250mm_ags:6143536
In: 02 2e verdieping
Classification: 21.11 buitenwanden; niet constructief, massieve wanden (Uniformat)
Pset_OpeningElementCommon - Reference: Constructie voids:Constructie voids; sets with these values: 2
Pset_ProductRequirements - Category: Walls

# IfcPlate: NLRS_32_CWP_schuifdeur_ags:Schuifdeur, NLRS_32_CWP_schuifdeur_ags:Schuifdeur:6245157
In: 01 1e verdieping
Type - PredefinedType: CURTAIN_PANEL; Classification: 31.32 buitenwandopeningen; gevuld met deuren, schuifdeuren (Uniformat); Material: NLRS_glas, Hout - Meranti
Type - Pset_PlateCommon - IsExternal: no
Type - Pset_ProductRequirements - Category: Curtain Panels
Classification: 32.40 binnenwandopeningen; gevuld met puien, algemeen (verzamelniveau) (Uniformat)
Pset_PlateCommon - Reference: NLRS_32_CWP_schuifdeur_ags:Schuifdeur
Pset_QuantityTakeOff - Reference: NLRS_32_CWP_schuifdeur_ags:Schuifdeur
BaseQuantities - NetVolume: 0.0517997 m3

# IfcPlate: System Panel:NLRS_31_CWP_geïsoleerd glas 25mm_ags, System Panel:NLRS_31_CWP_geïsoleerd glas 25mm_ags:6452089
In: 02 2e verdieping
Type - PredefinedType: CURTAIN_PANEL; Material: NLRS_glas
Type - Pset_PlateCommon - IsExternal: no
Type - Pset_ProductRequirements - Category: Curtain Panels
Classification: 32.40 binnenwandopeningen; gevuld met puien, algemeen (verzamelniveau) (Uniformat)
Pset_PlateCommon - Reference: System Panel:NLRS_31_CWP_geïsoleerd glas 25mm_ags
Pset_QuantityTakeOff - Reference: System Panel:NLRS_31_CWP_geïsoleerd glas 25mm_ags
BaseQuantities - NetVolume: 0.0043264 m3

# IfcRailing: Railing:NLRS_34_RAI_buisleuning balkon (10)
In: 02 2e verdieping
Classification: 34.21 balustrades en leuningen; leuningen, binnenleuningen (Uniformat)
Pset_ProductRequirements - Category: Railings
Pset_QuantityTakeOff - Reference: Railing:NLRS_34_RAI_buisleuning balkon
Pset_RailingCommon - IsExternal: no; Reference: Railing:NLRS_34_RAI_buisleuning balkon; Height: 1219.2 mm
Name (Railing:NLRS_34_RAI_buisleuning balkon:...) | Material | Length (mm)
6407088 | Default Metal (7), Default | 6293.87
6407378 | Default Metal (2), Default | 1224.73
6407574 | Default Metal (6), Default | 5228.32
6407581 | Default Metal (2), Default | 1224.73
6407636 | Default Metal (6), Default | 5384.01
6408014 | Default Metal (6), Default | 4987.2
6408310 | Default Metal (6), Default | 5384.01
6408321 | Default Metal (7), Default | 5988.74
6408560 | Default Metal (6), Default | 5371.46
6408774 | Default Metal (7), Default | 5988.74

# IfcRailing: Railing:NLRS_34_RAI_spijlenhekwerk hoofdtribune (22)
In: 01 1e verdieping
Classification: 34.21 balustrades en leuningen; leuningen, binnenleuningen (Uniformat)
Pset_ProductRequirements - Category: Railings
Pset_QuantityTakeOff - Reference: Railing:NLRS_34_RAI_spijlenhekwerk hoofdtribune
Pset_RailingCommon - IsExternal: no; Reference: Railing:NLRS_34_RAI_spijlenhekwerk hoofdtribune; Height: 1219.2 mm
Name (Railing:NLRS_34_RAI_spijlenhekwerk hoofdtribune:...) | Material | Length (mm)
6216300 | Default Metal (12) | 900
6218329 | Default Metal (12) | 900
6218349 | Default Metal (12) | 900
6218371 | Default Metal (12) | 900
6218393 | Default Metal (5) | 135.3
6218613 | Default Metal (12) | 900
6218622 | Default Metal (12) | 900
6218631 | Default Metal (12) | 900
6218640 | Default Metal (12) | 900
6218649 | Default Metal (5) | 135.3
6280325 | Default Metal (11) | 850
6280374 | Default Metal (11) | 850
6280765 | Default Metal (11) | 850
6280773 | Default Metal (11) | 850
6280781 | Default Metal (12) | 1100
6356070 | Default Metal (11) | 850
6356078 | Default Metal (11) | 850
6356094 | Default Metal (11) | 850
6356099 | Default Metal (11) | 850
6356199 | Default Metal (12) | 1100
6378264 | Default Metal (12) | 1100
6378271 | Default Metal (12) | 1100

# IfcSlab: Balkon midden:Balkon midden, Balkon midden:Balkon midden:6226785
In: 02 2e verdieping
Type - PredefinedType: FLOOR; Material: 20_APX_ontwerpmateriaal grijs
Type - Pset_ProductRequirements - Category: Floors
Type - Pset_SlabCommon - IsExternal: no
Pset_QuantityTakeOff - Reference: Balkon midden:Balkon midden; sets with these values: 2
Pset_SlabCommon - Reference: Balkon midden:Balkon midden
BaseQuantities - NetArea: 57.628 m2; NetVolume: 34.6518 m3

# IfcSlab: Balkon zijkanten1:Balkon zijkanten, Balkon zijkanten1:Balkon zijkanten:6305179
In: 02 2e verdieping
Type - PredefinedType: FLOOR; Material: 20_APX_ontwerpmateriaal grijs
Type - Pset_ProductRequirements - Category: Floors
Type - Pset_SlabCommon - IsExternal: no
Pset_QuantityTakeOff - Reference: Balkon zijkanten1:Balkon zijkanten; sets with these values: 2
Pset_SlabCommon - Reference: Balkon zijkanten1:Balkon zijkanten
BaseQuantities - GrossArea: 7.47205 m2; NetArea: 8.76724 m2; GrossVolume: 7.47205 m3; NetVolume: 8.11964 m3; Perimeter: 17819.9 mm; Width: 1000 mm

# IfcSlab: Balkon zijkanten:Balkon zijkanten, Balkon zijkanten:Balkon zijkanten:6264567
In: 02 2e verdieping
Type - PredefinedType: FLOOR; Material: 20_APX_ontwerpmateriaal grijs
Type - Pset_ProductRequirements - Category: Floors
Type - Pset_SlabCommon - IsExternal: no
Pset_QuantityTakeOff - Reference: Balkon zijkanten:Balkon zijkanten; sets with these values: 2
Pset_SlabCommon - Reference: Balkon zijkanten:Balkon zijkanten
BaseQuantities - GrossArea: 8.29182 m2; NetArea: 9.58701 m2; GrossVolume: 8.29182 m3; NetVolume: 8.93941 m3; Perimeter: 19545.8 mm; Width: 1000 mm

# IfcSlab: Floor:NLRS_23_FL_beton 200mm_ags, Floor:NLRS_23_FL_beton 200mm_ags:6140354
In: 02 2e verdieping
Type - PredefinedType: FLOOR; Material: NLRS_beton ihwg 200 mm
Type - Pset_ElementShading - Roughness: 304.8 mm
Type - Pset_ProductRequirements - Category: Floors
Type - Pset_ReinforcementBarPitchOfSlab - Description: Betonvloer 200mm
Type - Pset_SlabCommon - IsExternal: no
Classification: 23.20 vloeren; constructief, algemeen (verzamelniveau) (Uniformat)
Pset_QuantityTakeOff - Reference: Floor:NLRS_23_FL_beton 200mm_ags; sets with these values: 2
Pset_SlabCommon - LoadBearing: no; PitchAngle: 0 deg; Reference: Floor:NLRS_23_FL_beton 200mm_ags
BaseQuantities - GrossArea: 100.625 m2; NetArea: 100.625 m2; GrossVolume: 20.1249 m3; NetVolume: 20.1249 m3; Perimeter: 100025 mm; Width: 200 mm

# IfcSlab: Floor:NLRS_23_FL_beton 250mm_ags, Floor:NLRS_23_FL_beton 250mm_ags:6446159
In: 02 2e verdieping
Type - PredefinedType: FLOOR; Material: NLRS_beton ihwg 250 mm
Type - Pset_ElementShading - Roughness: 304.8 mm
Type - Pset_ProductRequirements - Category: Floors
Type - Pset_ReinforcementBarPitchOfSlab - Description: Betonvloer 250mm
Type - Pset_SlabCommon - IsExternal: no
Classification: 23.20 vloeren; constructief, algemeen (verzamelniveau) (Uniformat)
Pset_QuantityTakeOff - Reference: Floor:NLRS_23_FL_beton 250mm_ags; sets with these values: 2
Pset_SlabCommon - LoadBearing: no; PitchAngle: 0 deg; Reference: Floor:NLRS_23_FL_beton 250mm_ags
BaseQuantities - GrossArea: 196.509 m2; NetArea: 196.509 m2; GrossVolume: 49.1272 m3; NetVolume: 49.1265 m3; Perimeter: 146045 mm; Width: 250 mm

# IfcSlab: Floor:NLRS_23_FL_beton 350mm_ags (2)
In: 01 1e verdieping
Type - PredefinedType: FLOOR; Material: NLRS_beton ihwg 350 mm
Type - Pset_ElementShading - Roughness: 304.8 mm
Type - Pset_ProductRequirements - Category: Floors
Type - Pset_ReinforcementBarPitchOfSlab - Description: Betonvloer 350mm
Type - Pset_SlabCommon - IsExternal: no
Classification: 23.20 vloeren; constructief, algemeen (verzamelniveau) (Uniformat)
Pset_QuantityTakeOff - Reference: Floor:NLRS_23_FL_beton 350mm_ags; sets with these values: 2
Pset_SlabCommon - LoadBearing: no; Reference: Floor:NLRS_23_FL_beton 350mm_ags; PitchAngle: 0 deg
BaseQuantities - Width: 350 mm
Name (Floor:NLRS_23_FL_beton 350mm_ags:...) | GrossArea (m2) = NetArea (m2) | GrossVolume (m3) = NetVolume (m3) | Perimeter (mm)
6139446 | 425.061 | 148.771 | 171014
6291501 | 343.272 | 120.145 | 76087.6

# IfcSlab: Floor:NLRS_23_FL_multiplex 18mm_ags (2)
In: 02 2e verdieping
Type - PredefinedType: FLOOR; Material: NLRS_multiplex 18 mm
Type - Pset_ElementShading - Roughness: 304.8 mm
Type - Pset_ProductRequirements - Category: Floors
Type - Pset_ReinforcementBarPitchOfSlab - Description: Multiplex 18mm
Type - Pset_SlabCommon - IsExternal: no; ThermalTransmittance: 5.88889 kg/K/s3
Classification: 43.20 vloerafwerkingen; niet verhoogd, algemeen (verzamelniveau) (Uniformat)
Pset_QuantityTakeOff - Reference: Floor:NLRS_23_FL_multiplex 18mm_ags; sets with these values: 2
Pset_SlabCommon - LoadBearing: no; PitchAngle: 0 deg; Reference: Floor:NLRS_23_FL_multiplex 18mm_ags
BaseQuantities - Width: 18 mm
Name (Floor:NLRS_23_FL_multiplex 18mm_ags:...) | GrossArea (m2) = NetArea (m2) | GrossVolume (m3) = NetVolume (m3) | Perimeter (mm)
6452443 | 4.30041 | 0.0774073 | 12746.7
6458987 | 0.221917 | 0.00399451 | 2553.37

# IfcSlab: Floor:NLRS_23_FL_staalplaat - betonvloer 175mm_ags, Floor:NLRS_23_FL_staalplaat - betonvloer 175mm_ags:6144260
In: 03 3e verdieping
Type - PredefinedType: FLOOR; Material: NLRS_beton ihwg 175 mm
Type - Pset_ElementShading - Roughness: 304.8 mm
Type - Pset_ProductRequirements - Category: Floors
Type - Pset_ReinforcementBarPitchOfSlab - Description: Staalplaat - betonvloer 175mm
Type - Pset_SlabCommon - IsExternal: no
Classification: 23.20 vloeren; constructief, algemeen (verzamelniveau) (Uniformat)
Pset_QuantityTakeOff - Reference: Floor:NLRS_23_FL_staalplaat - betonvloer 175mm_ags; sets with these values: 2
Pset_SlabCommon - LoadBearing: no; PitchAngle: 0 deg; Reference: Floor:NLRS_23_FL_staalplaat - betonvloer 175mm_ags
BaseQuantities - GrossArea: 360.296 m2; NetArea: 360.296 m2; GrossVolume: 63.0518 m3; NetVolume: 63.0518 m3; Perimeter: 76031.7 mm; Width: 175 mm

# IfcSlab: Floor:NLRS_43_FL_dekvloer 50mm_ags (5)
Type - PredefinedType: FLOOR; Material: NLRS_dekvloer 50 mm
Type - Pset_ElementShading - Roughness: 304.8 mm
Type - Pset_ProductRequirements - Category: Floors
Type - Pset_ReinforcementBarPitchOfSlab - Description: Dekvloer 50 mm
Type - Pset_SlabCommon - IsExternal: no; ThermalTransmittance: 20.92 kg/K/s3
Classification: 23.10 vloeren; niet constructief, algemeen (verzamelniveau) (Uniformat)
Pset_QuantityTakeOff - Reference: Floor:NLRS_43_FL_dekvloer 50mm_ags; sets with these values: 2
Pset_SlabCommon - LoadBearing: no; PitchAngle: 0 deg; Reference: Floor:NLRS_43_FL_dekvloer 50mm_ags
BaseQuantities - Width: 50 mm
Name (Floor:NLRS_43_FL_dekvloer 50mm_ags:...) | In | GrossArea (m2) | NetArea (m2) | GrossVolume (m3) | NetVolume (m3) | Perimeter (mm)
6274388 | 02 2e verdieping | 88.2251 | 88.2251 | 4.41125 | 4.41125 | 100098
6306794 | 02 2e verdieping | 1.49527 | 1.49528 | 0.0747634 | 0.0747642 | 8238.14
6307437 | 02 2e verdieping | 1.49812 | 1.49812 | 0.074906 | 0.0749068 | 8325.07
6311613 | 02 2e verdieping | 196.509 | 196.509 | 9.82544 | 9.82531 | 146045
6423424 | 01 1e verdieping | 424.717 | 424.717 | 21.2358 | 21.2358 | 170947

# IfcSlab: Floor:NLRS_43_FL_gipsmontage 125mm_ags, Floor:NLRS_43_FL_gipsmontage 125mm_ags:6388375:3
In: 02 2e verdieping
Type - PredefinedType: FLOOR; Material: NLRS_gipsplaat 12.5 mm, NLRS_gipsplaat 12.5 mm, NLRS_aluminium C-profielen met isolatie 75 mm, NLRS_gipsplaat 12.5 mm, NLRS_gipsplaat 12.5 mm
Type - Pset_ElementShading - Roughness: 304.8 mm
Type - Pset_ProductRequirements - Category: Floors
Type - Pset_ReinforcementBarPitchOfSlab - Description: Gipsmontagevloer 125mm
Type - Pset_SlabCommon - IsExternal: no
Classification: 23.10 vloeren; niet constructief, algemeen (verzamelniveau) (Uniformat)
Pset_QuantityTakeOff - Reference: Floor:NLRS_43_FL_gipsmontage 125mm_ags; sets with these values: 2
Pset_SlabCommon - LoadBearing: no; PitchAngle: 0 deg; Reference: Floor:NLRS_43_FL_gipsmontage 125mm_ags
BaseQuantities - GrossArea: 4.78508 m2; NetArea: 14.8486 m2; NetVolume: 1.85608 m3; Perimeter: 36465.5 mm

# IfcSlab: Floor:NLRS_43_FL_gipsmontage 125mm_ags (2)
In: 02 2e verdieping
Type - PredefinedType: FLOOR
Type - Pset_ElementShading - Roughness: 304.8 mm
Type - Pset_ProductRequirements - Category: Floors
Type - Pset_ReinforcementBarPitchOfSlab - Description: Gipsmontagevloer 125mm
Type - Pset_SlabCommon - IsExternal: no
Classification: 23.10 vloeren; niet constructief, algemeen (verzamelniveau) (Uniformat); Material: NLRS_gipsplaat 12.5 mm, NLRS_gipsplaat 12.5 mm, NLRS_aluminium C-profielen met isolatie 75 mm, NLRS_gipsplaat 12.5 mm, NLRS_gipsplaat 12.5 mm
Pset_QuantityTakeOff - Reference: Floor:NLRS_43_FL_gipsmontage 125mm_ags; sets with these values: 2
Pset_SlabCommon - LoadBearing: no; PitchAngle: 0 deg; Reference: Floor:NLRS_43_FL_gipsmontage 125mm_ags
BaseQuantities - NetArea: 14.8486 m2; NetVolume: 1.85608 m3; Perimeter: 36465.5 mm
Name (Floor:NLRS_43_FL_gipsmontage 125mm_ags:...) | GrossArea (m2)
6388375 | 5.05111
6388375:2 | 5.01242

# IfcSlab: Floor:NLRS_43_FL_parketvloer zaal 97mm_ags (2)
In: 01 1e verdieping
Type - PredefinedType: FLOOR; Material: Hout - Keroewing 22 mm, Regelwerk 65 mm, Default 10 mm
Type - Pset_ElementShading - Roughness: 304.8 mm
Type - Pset_ProductRequirements - Category: Floors
Type - Pset_ReinforcementBarPitchOfSlab - Description: Parketvloer zaal 97mm
Type - Pset_SlabCommon - IsExternal: no; ThermalTransmittance: 4.81818 kg/K/s3
Classification: 43.20 vloerafwerkingen; niet verhoogd, algemeen (verzamelniveau) (Uniformat)
Pset_QuantityTakeOff - Reference: Floor:NLRS_43_FL_parketvloer zaal 97mm_ags; sets with these values: 2
Pset_SlabCommon - LoadBearing: no; PitchAngle: 0 deg; Reference: Floor:NLRS_43_FL_parketvloer zaal 97mm_ags
Name (Floor:NLRS_43_FL_parketvloer zaal 97mm_ags:...) | GrossArea (m2) | NetArea (m2) | NetVolume (m3) | Perimeter (mm)
6158458:2 | 113.871 | 316.228 | 30.6741 | 144241
6222776 | 126.567 | 12.6962 | 1.23153 | 120916

# IfcSlab: Floor:NLRS_43_FL_parketvloer zaal 97mm_ags, Floor:NLRS_43_FL_parketvloer zaal 97mm_ags:6158458
In: 01 1e verdieping
Type - PredefinedType: FLOOR
Type - Pset_ElementShading - Roughness: 304.8 mm
Type - Pset_ProductRequirements - Category: Floors
Type - Pset_ReinforcementBarPitchOfSlab - Description: Parketvloer zaal 97mm
Type - Pset_SlabCommon - IsExternal: no; ThermalTransmittance: 4.81818 kg/K/s3
Classification: 43.20 vloerafwerkingen; niet verhoogd, algemeen (verzamelniveau) (Uniformat); Material: Hout - Keroewing 22 mm, Regelwerk 65 mm, Default 10 mm
Pset_QuantityTakeOff - Reference: Floor:NLRS_43_FL_parketvloer zaal 97mm_ags; sets with these values: 2
Pset_SlabCommon - LoadBearing: no; PitchAngle: 0 deg; Reference: Floor:NLRS_43_FL_parketvloer zaal 97mm_ags
BaseQuantities - GrossArea: 202.356 m2; NetArea: 316.228 m2; NetVolume: 30.6741 m3; Perimeter: 144241 mm

# IfcSlab: Floor:NLRS_43_FL_roostervloer 30mm_ags, Floor:NLRS_43_FL_roostervloer 30mm_ags:6380821
In: 03 3e verdieping
Type - PredefinedType: FLOOR; Material: 21_APX_roostervloer 30 mm
Type - Pset_ElementShading - Roughness: 304.8 mm
Type - Pset_ProductRequirements - Category: Floors
Type - Pset_ReinforcementBarPitchOfSlab - Description: Roostervloer 30 mm
Type - Pset_SlabCommon - IsExternal: no
Classification: 23.10 vloeren; niet constructief, algemeen (verzamelniveau) (Uniformat)
Pset_QuantityTakeOff - Reference: Floor:NLRS_43_FL_roostervloer 30mm_ags; sets with these values: 2
Pset_SlabCommon - LoadBearing: no; PitchAngle: 0 deg; Reference: Floor:NLRS_43_FL_roostervloer 30mm_ags
BaseQuantities - GrossArea: 341.048 m2; NetArea: 101.789 m2; NetVolume: 3.0536 m3; Perimeter: 171128 mm

# IfcSlab: Hoofdtribune:Hoofdtribune, Hoofdtribune:Hoofdtribune:6194258
In: 01 1e verdieping
Type - PredefinedType: FLOOR; Material: 20_APX_ontwerpmateriaal grijs
Type - Pset_ProductRequirements - Category: Floors
Type - Pset_SlabCommon - IsExternal: no
Pset_QuantityTakeOff - Reference: Hoofdtribune:Hoofdtribune; sets with these values: 2
Pset_SlabCommon - Reference: Hoofdtribune:Hoofdtribune
BaseQuantities - NetArea: 107.118 m2; NetVolume: 124.089 m3

# IfcSlab: Tribune zijkanten:Tribune zijkanten, Tribune zijkanten:Tribune zijkanten:6239312
In: 01 1e verdieping
Type - PredefinedType: FLOOR; Material: 20_APX_ontwerpmateriaal grijs
Type - Pset_ProductRequirements - Category: Floors
Type - Pset_SlabCommon - IsExternal: no
Pset_QuantityTakeOff - Reference: Tribune zijkanten:Tribune zijkanten; sets with these values: 2
Pset_SlabCommon - Reference: Tribune zijkanten:Tribune zijkanten
BaseQuantities - GrossArea: 0.2 m2; NetArea: 34.68 m2; GrossVolume: 0.026 m3; NetVolume: 19.1046 m3; Perimeter: 2100 mm; Width: 130 mm

# IfcWall: Basic Wall:NLRS_21_WA_beton 250mm_ags (8)
Type - PredefinedType: STANDARD; Material: NLRS_beton ihwg 250 mm
Type - Pset_ElementShading - Roughness: 304.8 mm
Type - Pset_ProductRequirements - Category: Walls
Type - Pset_ReinforcementBarPitchOfWall - Description: Betonwand 250mm
Type - Pset_WallCommon - IsExternal: yes
Classification: 21.11 buitenwanden; niet constructief, massieve wanden (Uniformat)
Pset_QuantityTakeOff - Reference: Basic Wall:NLRS_21_WA_beton 250mm_ags; sets with these values: 2
Pset_WallCommon - Reference: Basic Wall:NLRS_21_WA_beton 250mm_ags; ExtendToStructure: no; LoadBearing: no
Name (Basic Wall:NLRS_21_WA_beton 250mm_ags:...) | In
6139364 | 01 1e verdieping
6141842 | 01 1e verdieping
6143541 | 02 2e verdieping
6143541 | 03 3e verdieping
6143542 | 02 2e verdieping
6143542 | 03 3e verdieping
6143549 | 02 2e verdieping
6143549 | 03 3e verdieping

# IfcWall: Basic Wall:NLRS_22_WA_akoestische voorzetwand 115mm 39-1-75_ags, Basic Wall:NLRS_22_WA_akoestische voorzetwand 115mm 39-1-75_ags:6256532
In: 01 1e verdieping
Type - PredefinedType: STANDARD; Material: NLRS_hout 39 mm, NLRS_vilt 1 mm, NLRS_aluminium C-profielen met isolatie 75 mm
Type - Pset_ElementShading - Roughness: 304.8 mm
Type - Pset_ProductRequirements - Category: Walls
Type - Pset_ReinforcementBarPitchOfWall - Description: Akoestische voorzetwand 115m
Type - Pset_WallCommon - IsExternal: no
Classification: 22.13 binnenwanden; niet constructief, systeemwanden; vast (Uniformat)
Pset_QuantityTakeOff - Reference: Basic Wall:NLRS_22_WA_akoestische voorzetwand 115mm 39-1-75_ags; sets with these values: 2
Pset_WallCommon - ExtendToStructure: no; LoadBearing: no; Reference: Basic Wall:NLRS_22_WA_akoestische voorzetwand 115mm 39-1-75_ags

# IfcWall: Basic Wall:NLRS_22_WA_ms-wand gips iso gips 100mm 25-50-25_ags, Basic Wall:NLRS_22_WA_ms-wand gips iso gips 100mm 25-50-25_ags:6282876
In: 01 1e verdieping
Type - PredefinedType: STANDARD; Material: NLRS_gipsplaat 12.5 mm, NLRS_gipsplaat 12.5 mm, NLRS_aluminium C-profielen met isolatie 50 mm, NLRS_gipsplaat 12.5 mm, NLRS_gipsplaat 12.5 mm
Type - Pset_ElementShading - Roughness: 304.8 mm
Type - Pset_ProductRequirements - Category: Walls
Type - Pset_ReinforcementBarPitchOfWall - Description: Gipsmontagewand 100 mm geisoleerd dubbele plaat
Type - Pset_WallCommon - IsExternal: no
Classification: 22.13 binnenwanden; niet constructief, systeemwanden; vast (Uniformat)
Pset_QuantityTakeOff - Reference: Basic Wall:NLRS_22_WA_ms-wand gips iso gips 100mm 25-50-25_ags; sets with these values: 2
Pset_WallCommon - ExtendToStructure: no; LoadBearing: no; Reference: Basic Wall:NLRS_22_WA_ms-wand gips iso gips 100mm 25-50-25_ags

# IfcWall: Basic Wall:NLRS_42_WA_multiplex 13mm_ags (2)
In: 02 2e verdieping
Type - PredefinedType: STANDARD; Material: NLRS_multiplex 13 mm
Type - Pset_ElementShading - Roughness: 304.8 mm
Type - Pset_ProductRequirements - Category: Walls
Type - Pset_ReinforcementBarPitchOfWall - Description: Multiplex 13mm
Type - Pset_WallCommon - IsExternal: no; ThermalTransmittance: 8.15385 kg/K/s3
Classification: 42.12 binnenwandafwerkingen; bekledingen (Uniformat)
Pset_QuantityTakeOff - Reference: Basic Wall:NLRS_42_WA_multiplex 13mm_ags; sets with these values: 2
Pset_WallCommon - ExtendToStructure: no; LoadBearing: no; Reference: Basic Wall:NLRS_42_WA_multiplex 13mm_ags
Name (Basic Wall:NLRS_42_WA_multiplex 13mm_ags:...)
6163274
6288440

# IfcWall: Basic Wall:NLRS_42_WA_multiplex 18mm_ags (2)
In: 02 2e verdieping
Type - PredefinedType: STANDARD; Material: NLRS_multiplex 18 mm
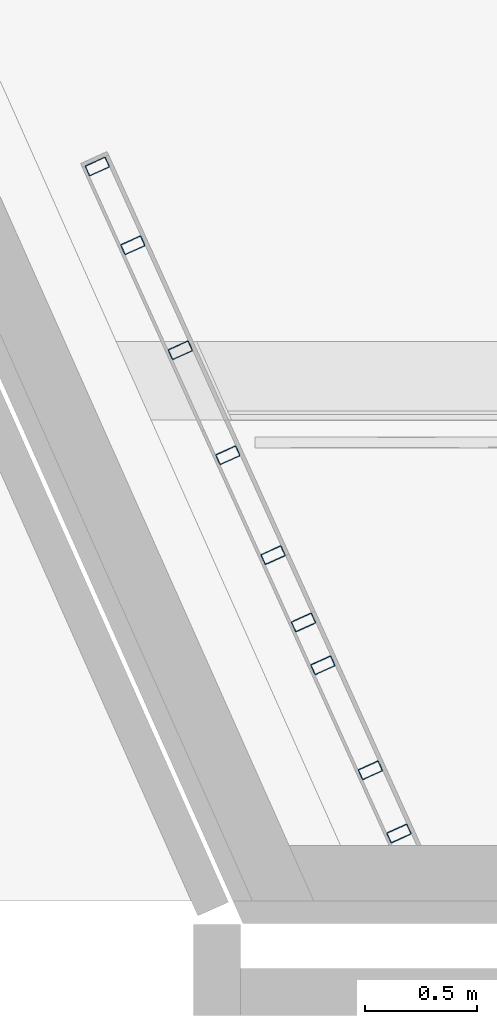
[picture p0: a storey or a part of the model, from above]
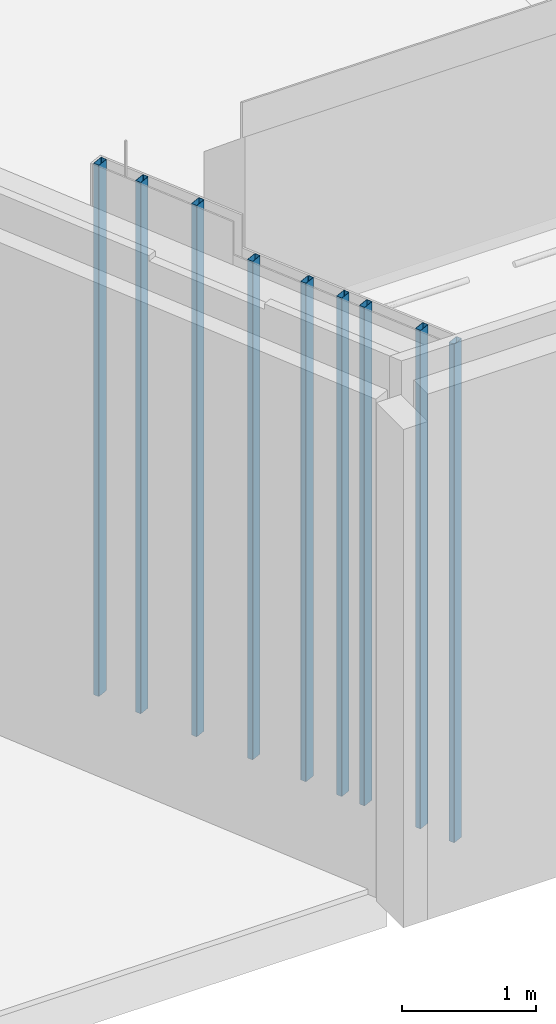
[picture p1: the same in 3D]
Properties of the parts of a building model (IFC2X3), part 2 of 2

# IfcWall: Basic Wall:NLRS_42_WA_multiplex 18mm_ags (2)
Type - Pset_ElementShading - Roughness: 304.8 mm
Type - Pset_ProductRequirements - Category: Walls
Type - Pset_ReinforcementBarPitchOfWall - Description: Multiplex 18mm
Type - Pset_WallCommon - IsExternal: no; ThermalTransmittance: 5.88889 kg/K/s3
Classification: 42.12 binnenwandafwerkingen; bekledingen (Uniformat)
Pset_QuantityTakeOff - Reference: Basic Wall:NLRS_42_WA_multiplex 18mm_ags; sets with these values: 2
Pset_WallCommon - ExtendToStructure: no; LoadBearing: no; Reference: Basic Wall:NLRS_42_WA_multiplex 18mm_ags
Name (Basic Wall:NLRS_42_WA_multiplex 18mm_ags:...)
6164579
6286905

# IfcWall: Vloerrand balkon1:Vloerrand balkon, Vloerrand balkon1:Vloerrand balkon:6478785
In: 01 1e verdieping
Type - Material: 20_APX_ontwerpmateriaal grijs
Type - Pset_ProductRequirements - Category: Walls
Type - Pset_WallCommon - IsExternal: no
Pset_QuantityTakeOff - Reference: Vloerrand balkon1:Vloerrand balkon; sets with these values: 2
Pset_WallCommon - Reference: Vloerrand balkon1:Vloerrand balkon

# IfcWall: Vloerrand balkon:Vloerrand balkon, Vloerrand balkon:Vloerrand balkon:6269056
In: 01 1e verdieping
Type - Material: 31_APX_Glas
Type - Pset_ProductRequirements - Category: Walls
Type - Pset_WallCommon - IsExternal: no
Pset_QuantityTakeOff - Reference: Vloerrand balkon:Vloerrand balkon; sets with these values: 2
Pset_WallCommon - Reference: Vloerrand balkon:Vloerrand balkon

# IfcWallStandardCase: Basic Wall:NLRS_21_WA_beton 250mm_ags (22)
Type - PredefinedType: STANDARD; Material: NLRS_beton ihwg 250 mm
Type - Pset_ElementShading - Roughness: 304.8 mm
Type - Pset_ProductRequirements - Category: Walls
Type - Pset_ReinforcementBarPitchOfWall - Description: Betonwand 250mm
Type - Pset_WallCommon - IsExternal: yes
Classification: 21.11 buitenwanden; niet constructief, massieve wanden (Uniformat)
BaseQuantities - Width: 250 mm
Pset_QuantityTakeOff - Reference: Basic Wall:NLRS_21_WA_beton 250mm_ags; sets with these values: 2
Pset_WallCommon - Reference: Basic Wall:NLRS_21_WA_beton 250mm_ags; ExtendToStructure: no; LoadBearing: no
Name (Basic Wall:NLRS_21_WA_beton 250mm_ags:...) | In | Height (mm) | Length (mm) | GrossFootprintArea (m2) | GrossVolume (m3) | GrossSideArea (m2) = NetSideArea (m2) | NetVolume (m3)
6135947 | 01 1e verdieping | 4600 | 10616.3 | 2.61 | 12.0807 | 48.3228 | 12.006
6137919 | 01 1e verdieping | 4800 | 6816.38 | 1.61999 | 7.60246 | 30.4098 | 7.19877
6138007 | 01 1e verdieping | 4800 | 8094.7 | 1.8833 | 8.69244 | 34.7698 | 8.01863
6138079 | 01 1e verdieping | 4800 | 8900.91 | 2.14112 | 9.25902 | 37.0361 | 8.85533
6138162 | 01 1e verdieping | 4600 | 13032.5 | 3.21296 | 14.8594 | 59.4374 | 14.7796
6138607 | 01 1e verdieping | 4600 | 11797.6 | 2.92286 | 13.5673 | 54.2692 | 13.4451
6140540 | 01 1e verdieping | 4600 | 12153.8 | 3.01254 | 13.9769 | 55.9075 | 13.8577
6140967 | 01 1e verdieping | 4600 | 2162.72 | 0.497434 | 1.89605 | 7.5842 | 1.69712
6143536 | 02 2e verdieping | 3650 | 10963.7 | 2.69107 | 9.80661 | 39.2265 | 9.81893
6143536 | 03 3e verdieping | 3550 | 10963.7 | 2.69107 | 9.12153 | 36.4861 | 9.06388
6143537 | 02 2e verdieping | 3650 | 6816.38 | 1.61999 | 5.6483 | 22.5932 | 5.34133
6143537 | 03 3e verdieping | 3550 | 6816.38 | 1.61999 | 6.04954 | 24.1982 | 5.75098
6143538 | 02 2e verdieping | 3650 | 8094.7 | 1.8833 | 7.38641 | 29.5457 | 6.87404
6143538 | 03 3e verdieping | 3550 | 8094.7 | 1.8833 | 7.18405 | 28.7362 | 6.68571
6143539 | 02 2e verdieping | 3650 | 8900.91 | 2.14112 | 7.531 | 30.124 | 7.22403
6143539 | 03 3e verdieping | 3550 | 8900.91 | 2.14112 | 7.89955 | 31.5982 | 7.60099
6143540 | 02 2e verdieping | 3650 | 13032.5 | 3.21296 | 11.7906 | 47.1623 | 11.7273
6143540 | 03 3e verdieping | 3550 | 13032.5 | 3.21296 | 11.4675 | 45.8702 | 11.406
6143543 | 02 2e verdieping | 3650 | 12153.8 | 3.01254 | 11.0904 | 44.3614 | 10.9958
6143543 | 03 3e verdieping | 3550 | 12153.8 | 3.01254 | 10.7865 | 43.146 | 10.6945
6143544 | 02 2e verdieping | 3650 | 2162.72 | 0.497434 | 1.3824 | 5.52962 | 1.22456
6143544 | 03 3e verdieping | 3550 | 2162.72 | 0.497434 | 1.91941 | 7.67765 | 1.76589

# IfcWallStandardCase: Basic Wall:NLRS_21_WA_isolatie 100mm_ags (3)
Type - PredefinedType: STANDARD; Material: NLRS_isolatie 100 mm
Type - Pset_ElementShading - Roughness: 304.8 mm
Type - Pset_ProductRequirements - Category: Walls
Type - Pset_ReinforcementBarPitchOfWall - Description: Isolatie 100mm
Type - Pset_WallCommon - IsExternal: yes
Classification: 21.10 buitenwanden; niet constructief, algemeen (verzamelniveau) (Uniformat)
BaseQuantities - Length: 13849.1 mm; Width: 100 mm; GrossFootprintArea: 1.37768 m2
Pset_QuantityTakeOff - Reference: Basic Wall:NLRS_21_WA_isolatie 100mm_ags; sets with these values: 2
Pset_WallCommon - ExtendToStructure: no; LoadBearing: no; Reference: Basic Wall:NLRS_21_WA_isolatie 100mm_ags
Name (Basic Wall:NLRS_21_WA_isolatie 100mm_ags:...) | In | Height (mm) | GrossVolume (m3) | GrossSideArea (m2) = NetSideArea (m2) | NetVolume (m3)
6156775 | 01 1e verdieping | 4850 | 6.69522 | 66.9522 | 6.68177
6156775 | 02 2e verdieping | 3600 | 4.96965 | 49.6965 | 4.95966
6156775 | 03 3e verdieping | 3550 | 4.90062 | 49.0062 | 4.89078

# IfcWallStandardCase: Basic Wall:NLRS_21_WA_isolatie 80mm_ags (27)
Type - PredefinedType: STANDARD; Material: NLRS_isolatie 80 mm
Type - Pset_ElementShading - Roughness: 304.8 mm
Type - Pset_ProductRequirements - Category: Walls
Type - Pset_ReinforcementBarPitchOfWall - Description: Isolatie 80mm
Type - Pset_WallCommon - IsExternal: yes
Classification: 21.10 buitenwanden; niet constructief, algemeen (verzamelniveau) (Uniformat)
BaseQuantities - Width: 80 mm
Pset_QuantityTakeOff - Reference: Basic Wall:NLRS_21_WA_isolatie 80mm_ags; sets with these values: 2
Pset_WallCommon - ExtendToStructure: no; LoadBearing: no; Reference: Basic Wall:NLRS_21_WA_isolatie 80mm_ags
Name (Basic Wall:NLRS_21_WA_isolatie 80mm_ags:...) | In | Height (mm) | Length (mm) | GrossFootprintArea (m2) | GrossVolume (m3) | GrossSideArea (m2) = NetSideArea (m2) | NetVolume (m3)
6156949 | 01 1e verdieping | 4850 | 10669.7 | 0.849066 | 4.12604 | 51.5754 | 4.11797
6156949 | 02 2e verdieping | 3600 | 10669.7 | 0.849066 | 3.05886 | 38.2358 | 3.05288
6156949 | 03 3e verdieping | 3550 | 10669.7 | 0.849066 | 2.8569 | 35.7113 | 2.851
6157103 | 01 1e verdieping | 4850 | 6613.91 | 0.520501 | 2.37737 | 29.7172 | 2.33561
6157103 | 02 2e verdieping | 3600 | 6613.91 | 0.520501 | 1.726 | 21.575 | 1.695
6157103 | 03 3e verdieping | 3550 | 6613.91 | 0.520501 | 1.87835 | 23.4794 | 1.84778
6157210 | 01 1e verdieping | 4850 | 7783.02 | 0.608267 | 2.69303 | 33.6628 | 2.62331
6157210 | 02 2e verdieping | 3600 | 7783.02 | 0.608267 | 2.24151 | 28.0189 | 2.18976
6157210 | 03 3e verdieping | 3550 | 7783.02 | 0.608267 | 2.21038 | 27.6297 | 2.15935
6157323 | 01 1e verdieping | 4850 | 8842.74 | 0.698807 | 2.97166 | 37.1458 | 2.92989
6157323 | 02 2e verdieping | 3600 | 8842.74 | 0.698807 | 2.3617 | 29.5213 | 2.3307
6157323 | 03 3e verdieping | 3550 | 8842.74 | 0.698807 | 2.51134 | 31.3917 | 2.48076
6157425 | 01 1e verdieping | 4850 | 12307.7 | 0.981964 | 4.77539 | 59.6924 | 4.76252
6157425 | 02 2e verdieping | 3600 | 12307.7 | 0.981964 | 3.54462 | 44.3078 | 3.53507
6157425 | 03 3e verdieping | 3550 | 12307.7 | 0.981964 | 3.49539 | 43.6924 | 3.48597
6157492 | 01 1e verdieping | 4850 | 11678.3 | 0.931542 | 4.53117 | 56.6396 | 4.51798
6157492 | 02 2e verdieping | 3600 | 11678.3 | 0.931542 | 3.36334 | 42.0417 | 3.35355
6157492 | 03 3e verdieping | 3550 | 11678.3 | 0.931542 | 3.31663 | 41.4578 | 3.30697
6157533 | 01 1e verdieping | 4850 | 1536.87 | 0.1201 | 0.411072 | 5.1384 | 0.397252
6157533 | 02 2e verdieping | 3600 | 1536.87 | 0.1201 | 0.265545 | 3.31932 | 0.255287
6157533 | 03 3e verdieping | 3550 | 1536.87 | 0.1201 | 0.43647 | 5.45588 | 0.426354
6157612 | 01 1e verdieping | 4850 | 1919.95 | 0.149168 | 0.551536 | 6.8942 | 0.530058
6157612 | 02 2e verdieping | 3600 | 1919.95 | 0.149168 | 0.368061 | 4.60076 | 0.352119
6157612 | 03 3e verdieping | 3550 | 1919.95 | 0.149168 | 0.545265 | 6.81582 | 0.529545
6157723 | 01 1e verdieping | 4850 | 2004.55 | 0.155982 | 0.505407 | 6.31759 | 0.484154
6157723 | 02 2e verdieping | 3600 | 2004.55 | 0.155982 | 0.316951 | 3.96188 | 0.301175
6157723 | 03 3e verdieping | 3550 | 2004.55 | 0.155982 | 0.569291 | 7.11614 | 0.553734

# IfcWallStandardCase: Basic Wall:NLRS_21_WA_metselwerk 210mm_ags (6)
Type - PredefinedType: STANDARD; Material: NLRS_metselwerk schoonwerk 210 mm
Type - Pset_ElementShading - Roughness: 304.8 mm
Type - Pset_ProductRequirements - Category: Walls
Type - Pset_ReinforcementBarPitchOfWall - Description: Metselwerk 210mm
Type - Pset_WallCommon - IsExternal: yes
Classification: 21.11 buitenwanden; niet constructief, massieve wanden (Uniformat)
BaseQuantities - Width: 210 mm
Pset_QuantityTakeOff - Reference: Basic Wall:NLRS_21_WA_metselwerk 210mm_ags; sets with these values: 2
Pset_WallCommon - ExtendToStructure: no; LoadBearing: no; Reference: Basic Wall:NLRS_21_WA_metselwerk 210mm_ags
Name (Basic Wall:NLRS_21_WA_metselwerk 210mm_ags:...) | In | Height (mm) | Length (mm) | GrossFootprintArea (m2) | GrossVolume (m3) | GrossSideArea (m2) = NetSideArea (m2) | NetVolume (m3)
6144488 | 02 2e verdieping | 3650 | 14254.5 | 2.99344 | 10.926 | 52.0288 | 10.926
6144488 | 03 3e verdieping | 3550 | 14254.5 | 2.99344 | 10.6267 | 50.6033 | 10.6267
6296146 | 02 2e verdieping | 3650 | 300.014 | 0.063003 | 0.229961 | 1.09505 | 0.229961
6296146 | 03 3e verdieping | 3550 | 300.014 | 0.063003 | 0.223661 | 1.06505 | 0.223661
6359914 | 01 1e verdieping | 4800 | 14465.5 | 3.01571 | 14.5813 | 69.4345 | 14.4754
6359915 | 01 1e verdieping | 4550 | 405.014 | 0.085053 | 0.386991 | 1.84282 | 0.386991

# IfcWallStandardCase: Basic Wall:NLRS_22_WA_akoestisch wandelement 100mm_ags (6)
In: 01 1e verdieping
Type - PredefinedType: STANDARD; Material: 20_APX_ontwerpmateriaal grijs 100 mm
Type - Pset_ElementShading - Roughness: 304.8 mm
Type - Pset_ProductRequirements - Category: Walls
Type - Pset_ReinforcementBarPitchOfWall - Description: Akoestisch wandelement 100mm
Type - Pset_WallCommon - IsExternal: no
Classification: 48.10 afwerkingspakketten; algemeen (verzamelniveau) (Uniformat)
BaseQuantities - Height: 1275 mm; Length: 600 mm; Width: 100 mm; GrossFootprintArea: 0.06 m2; GrossVolume: 0.0765 m3; GrossSideArea: 0.765 m2; NetSideArea: 0.765 m2; NetVolume: 0.0765 m3
Pset_QuantityTakeOff - Reference: Basic Wall:NLRS_22_WA_akoestisch wandelement 100mm_ags; sets with these values: 2
Pset_WallCommon - ExtendToStructure: no; LoadBearing: no; Reference: Basic Wall:NLRS_22_WA_akoestisch wandelement 100mm_ags
Name (Basic Wall:NLRS_22_WA_akoestisch wandelement 100mm_ags:...)
6289353
6289768
6289776
6289784
6289792
6289967

# IfcWallStandardCase: Basic Wall:NLRS_22_WA_akoestische voorzetwand 115mm 39-1-75_ags (9)
In: 01 1e verdieping
Type - PredefinedType: STANDARD; Material: NLRS_hout 39 mm, NLRS_vilt 1 mm, NLRS_aluminium C-profielen met isolatie 75 mm
Type - Pset_ElementShading - Roughness: 304.8 mm
Type - Pset_ProductRequirements - Category: Walls
Type - Pset_ReinforcementBarPitchOfWall - Description: Akoestische voorzetwand 115m
Type - Pset_WallCommon - IsExternal: no
Classification: 22.13 binnenwanden; niet constructief, systeemwanden; vast (Uniformat)
BaseQuantities - Height: 2705 mm; Width: 115 mm
Pset_QuantityTakeOff - Reference: Basic Wall:NLRS_22_WA_akoestische voorzetwand 115mm 39-1-75_ags; sets with these values: 2
Pset_WallCommon - ExtendToStructure: no; LoadBearing: no; Reference: Basic Wall:NLRS_22_WA_akoestische voorzetwand 115mm 39-1-75_ags
Name (Basic Wall:NLRS_22_WA_akoestische voorzetwand 115mm 39-1-75_ags:...) | Length (mm) | GrossFootprintArea (m2) | GrossVolume (m3) | GrossSideArea (m2) = NetSideArea (m2) | NetVolume (m3)
6256955 | 1099.86 | 0.111632 | 0.34214 | 2.97513 | 0.301966
6258089 | 1382.74 | 0.144163 | 0.430135 | 3.74031 | 0.389961
6258242 | 1100 | 0.1265 | 0.342182 | 2.9755 | 0.342183
6258561 | 1100 | 0.1265 | 0.342183 | 2.9755 | 0.342182
6258858 | 1100 | 0.1265 | 0.342182 | 2.9755 | 0.342182
6259404 | 1100 | 0.1265 | 0.342182 | 2.9755 | 0.342182
6259684 | 1100 | 0.1265 | 0.342182 | 2.9755 | 0.342182
6259899 | 1100 | 0.1265 | 0.342183 | 2.9755 | 0.342182
6260178 | 1382.74 | 0.144163 | 0.430135 | 3.74031 | 0.389961

# IfcWallStandardCase: Basic Wall:NLRS_22_WA_akoestische voorzetwand 190mm 39-1-150_ags (8)
In: 02 2e verdieping
Type - PredefinedType: STANDARD; Material: NLRS_hout 39 mm, NLRS_vilt 1 mm, NLRS_aluminium C-profielen met isolatie 150 mm
Type - Pset_ElementShading - Roughness: 304.8 mm
Type - Pset_ProductRequirements - Category: Walls
Type - Pset_ReinforcementBarPitchOfWall - Description: Akoestische voorzetwand 190m
Type - Pset_WallCommon - IsExternal: no
Classification: 22.13 binnenwanden; niet constructief, systeemwanden; vast (Uniformat)
BaseQuantities - Height: 2200 mm; Length: 1100 mm; Width: 190 mm; GrossFootprintArea: 0.209 m2; GrossVolume: 0.4598 m3; GrossSideArea: 2.42 m2; NetSideArea: 2.42 m2; NetVolume: 0.4598 m3
Pset_QuantityTakeOff - Reference: Basic Wall:NLRS_22_WA_akoestische voorzetwand 190mm 39-1-150_ags; sets with these values: 2
Pset_WallCommon - ExtendToStructure: no; LoadBearing: no; Reference: Basic Wall:NLRS_22_WA_akoestische voorzetwand 190mm 39-1-150_ags
Name (Basic Wall:NLRS_22_WA_akoestische voorzetwand 190mm 39-1-150_ags:...)
6283698
6283700
6283703
6283705
6284867
6285627
6285886
6286068

# IfcWallStandardCase: Basic Wall:NLRS_22_WA_kalkzandsteen 150mm_ags (27)
Type - PredefinedType: STANDARD; Material: NLRS_kalkzandsteen 150 mm
Type - Pset_ElementShading - Roughness: 304.8 mm
Type - Pset_ProductRequirements - Category: Walls
Type - Pset_ReinforcementBarPitchOfWall - Description: Kalkzandsteen 150mm
Type - Pset_WallCommon - IsExternal: no
Classification: 22.11 binnenwanden; niet constructief, massieve wanden (Uniformat)
BaseQuantities - Width: 150 mm
Pset_QuantityTakeOff - Reference: Basic Wall:NLRS_22_WA_kalkzandsteen 150mm_ags; sets with these values: 2
Pset_WallCommon - ExtendToStructure: no; LoadBearing: no; Reference: Basic Wall:NLRS_22_WA_kalkzandsteen 150mm_ags
Name (Basic Wall:NLRS_22_WA_kalkzandsteen 150mm_ags:...) | In | Height (mm) | Length (mm) | GrossFootprintArea (m2) | GrossVolume (m3) | GrossSideArea (m2) | NetSideArea (m2) | NetVolume (m3)
6136175 | 01 1e verdieping | 4550 | 10628 | 1.57834 | 7.20805 | 48.0537 | 48.0537 | 7.18145
6138243 | 01 1e verdieping | 4550 | 6872.21 | 1.00055 | 4.34396 | 28.9598 | 28.9598 | 4.2062
6138328 | 01 1e verdieping | 4550 | 7997.63 | 1.14911 | 5.45838 | 36.3892 | 32.3964 | 4.62953
6138469 | 01 1e verdieping | 4550 | 8824.06 | 1.29834 | 5.16918 | 34.4612 | 34.4612 | 5.05421
6138796 | 01 1e verdieping | 4550 | 2479.12 | 0.356462 | 1.19258 | 7.95053 | 7.95053 | 1.12248
6138861 | 01 1e verdieping | 4550 | 11570.5 | 1.72602 | 7.8969 | 52.646 | 52.646 | 7.8534
6142320 | 01 1e verdieping | 4550 | 1940 | 0.280983 | 0.984387 | 6.56258 | 6.56258 | 0.938814
6142421 | 01 1e verdieping | 4550 | 12203.3 | 1.82117 | 8.32876 | 55.5251 | 55.5251 | 8.28632
6142474 | 01 1e verdieping | 4550 | 2556.52 | 0.367907 | 1.39018 | 9.26785 | 9.26785 | 1.31933
6144485 | 02 2e verdieping | 3650 | 10836.5 | 1.60961 | 5.88936 | 39.2624 | 39.2624 | 5.86802
6144485 | 03 3e verdieping | 3550 | 10836.5 | 1.60961 | 5.42889 | 36.1926 | 36.1926 | 5.40814
6144486 | 02 2e verdieping | 3650 | 6872.21 | 1.00055 | 3.41955 | 22.797 | 22.797 | 3.30904
6144486 | 03 3e verdieping | 3550 | 6872.21 | 1.00055 | 3.65945 | 24.3963 | 24.3963 | 3.55197
6144487 | 02 2e verdieping | 3650 | 7997.63 | 1.14911 | 4.3787 | 29.1914 | 29.1914 | 4.19425
6144487 | 03 3e verdieping | 3550 | 7997.63 | 1.14911 | 4.25874 | 28.3916 | 28.3916 | 4.07934
6144489 | 02 2e verdieping | 3650 | 8777.46 | 1.26608 | 4.26656 | 28.4437 | 28.4437 | 4.26656
6144489 | 03 3e verdieping | 3550 | 8777.46 | 1.26608 | 4.49459 | 29.964 | 29.964 | 4.49459
6144490 | 02 2e verdieping | 3650 | 2270.68 | 0.325196 | 1.2432 | 8.28797 | 5.03349 | 0.713763
6144490 | 03 3e verdieping | 3550 | 2270.68 | 0.325196 | 1.20914 | 8.0609 | 8.0609 | 1.15444
6144491 | 02 2e verdieping | 3650 | 11734.7 | 1.75065 | 6.42477 | 42.8318 | 42.8318 | 6.38988
6144491 | 03 3e verdieping | 3550 | 11734.7 | 1.75065 | 6.24875 | 41.6583 | 41.6583 | 6.21481
6144492 | 02 2e verdieping | 3650 | 1775.81 | 0.256355 | 0.972259 | 6.48172 | 4.26832 | 0.608819
6144492 | 03 3e verdieping | 3550 | 1775.81 | 0.256355 | 0.945621 | 6.30414 | 6.30414 | 0.910059
6144493 | 02 2e verdieping | 3650 | 12363.4 | 1.84519 | 6.76898 | 45.1265 | 45.1265 | 6.73494
6144493 | 03 3e verdieping | 3550 | 12363.4 | 1.84519 | 6.58353 | 43.8902 | 43.8902 | 6.55042
6144494 | 02 2e verdieping | 3650 | 2188.45 | 0.32395 | 1.19818 | 7.98786 | 5.67681 | 0.835784
6144494 | 03 3e verdieping | 3550 | 2188.45 | 0.32395 | 1.16535 | 7.76901 | 7.76901 | 1.15002

# IfcWallStandardCase: Basic Wall:NLRS_22_WA_ms-wand gips gips 150mm 25-100-25_ags (2)
In: 02 2e verdieping
Type - PredefinedType: STANDARD; Material: NLRS_gipsplaat 12.5 mm, NLRS_gipsplaat 12.5 mm, NLRS_aluminium C-profielen 100 mm, NLRS_gipsplaat 12.5 mm, NLRS_gipsplaat 12.5 mm
Type - Pset_ElementShading - Roughness: 304.8 mm
Type - Pset_ProductRequirements - Category: Walls
Type - Pset_ReinforcementBarPitchOfWall - Description: Gipsmontagewand 150 mm dubbele plaat tweezijdig
Type - Pset_WallCommon - IsExternal: no
Classification: 22.13 binnenwanden; niet constructief, systeemwanden; vast (Uniformat)
BaseQuantities - Height: 3400 mm; Width: 150 mm
Pset_QuantityTakeOff - Reference: Basic Wall:NLRS_22_WA_ms-wand gips gips 150mm 25-100-25_ags; sets with these values: 2
Pset_WallCommon - ExtendToStructure: no; LoadBearing: no; Reference: Basic Wall:NLRS_22_WA_ms-wand gips gips 150mm 25-100-25_ags
Name (Basic Wall:NLRS_22_WA_ms-wand gips gips 150mm 25-100-25_ags:...) | Length (mm) | GrossFootprintArea (m2) | GrossVolume (m3) | GrossSideArea (m2) = NetSideArea (m2) | NetVolume (m3)
6427517 | 636.884 | 0.0855142 | 0.290751 | 1.93834 | 0.290748
6427810 | 499.736 | 0.0648617 | 0.220806 | 1.47204 | 0.22053

# IfcWallStandardCase: Basic Wall:NLRS_22_WA_ms-wand gips iso 100mm 25-75_ags (13)
Type - PredefinedType: STANDARD; Material: NLRS_gipsplaat 12.5 mm, NLRS_gipsplaat 12.5 mm, NLRS_aluminium C-profielen met isolatie 75 mm
Type - Pset_ElementShading - Roughness: 304.8 mm
Type - Pset_ProductRequirements - Category: Walls
Type - Pset_ReinforcementBarPitchOfWall - Description: Gipsmontagewand 100 mm geisoleerd dubbele plaat enkelzijdig
Type - Pset_WallCommon - IsExternal: no
Classification: 22.13 binnenwanden; niet constructief, systeemwanden; vast (Uniformat)
BaseQuantities - Width: 100 mm
Pset_QuantityTakeOff - Reference: Basic Wall:NLRS_22_WA_ms-wand gips iso 100mm 25-75_ags; sets with these values: 2
Pset_WallCommon - ExtendToStructure: no; LoadBearing: no; Reference: Basic Wall:NLRS_22_WA_ms-wand gips iso 100mm 25-75_ags
Name (Basic Wall:NLRS_22_WA_ms-wand gips iso 100mm 25-75_ags:...) | In | Height (mm) | Length (mm) | GrossFootprintArea (m2) | GrossVolume (m3) | GrossSideArea (m2) = NetSideArea (m2) | NetVolume (m3)
6147857 | 01 1e verdieping | 4500 | 827.535 | 0.0798667 | 0.372391 | 3.72391 | 0.3594
6149481 | 01 1e verdieping | 4500 | 827.535 | 0.0798667 | 0.372391 | 3.72391 | 0.3594
6152044 | 01 1e verdieping | 2170 | 1840 | 0.184 | 0.39928 | 3.9928 | 0.39928
6152247 | 01 1e verdieping | 2170 | 1840 | 0.184 | 0.39928 | 3.9928 | 0.39928
6225280 | 02 2e verdieping | 3200 | 827.535 | 0.0798667 | 0.264811 | 2.64811 | 0.255573
6225748 | 02 2e verdieping | 3200 | 827.535 | 0.0798667 | 0.264811 | 2.64811 | 0.255573
6397531 | 01 1e verdieping | 4500 | 1522.38 | 0.141725 | 0.685071 | 6.85071 | 0.637763
6397744 | 01 1e verdieping | 4500 | 1072.71 | 0.0924033 | 0.450015 | 4.50015 | 0.415815
6398098 | 01 1e verdieping | 4500 | 1057.83 | 0.0895496 | 0.431025 | 4.31025 | 0.402973
6425858 | 02 2e verdieping | 3200 | 1522.38 | 0.141725 | 0.487162 | 4.87162 | 0.45352
6425859 | 02 2e verdieping | 3200 | 783.806 | 0.0602667 | 0.250818 | 2.50818 | 0.192853
6425860 | 02 2e verdieping | 3200 | 1057.83 | 0.0895496 | 0.306507 | 3.06507 | 0.286559
6440866 | 02 2e verdieping | 3200 | 312.522 | 0.024372 | 0.100007 | 1.00007 | 0.0779903

# IfcWallStandardCase: Basic Wall:NLRS_22_WA_ms-wand gips iso gips 125mm 25-75-25_ags (4)
Type - PredefinedType: STANDARD; Material: NLRS_gipsplaat 12.5 mm, NLRS_gipsplaat 12.5 mm, NLRS_aluminium C-profielen met isolatie 75 mm, NLRS_gipsplaat 12.5 mm, NLRS_gipsplaat 12.5 mm
Type - Pset_ElementShading - Roughness: 304.8 mm
Type - Pset_ProductRequirements - Category: Walls
Type - Pset_ReinforcementBarPitchOfWall - Description: Gipsmontagewand 125 mm geisoleerd dubbele plaat tweezijdig
Type - Pset_WallCommon - IsExternal: no
Classification: 22.13 binnenwanden; niet constructief, systeemwanden; vast (Uniformat)
BaseQuantities - Width: 125 mm
Pset_QuantityTakeOff - Reference: Basic Wall:NLRS_22_WA_ms-wand gips iso gips 125mm 25-75-25_ags; sets with these values: 2
Pset_WallCommon - ExtendToStructure: no; LoadBearing: no; Reference: Basic Wall:NLRS_22_WA_ms-wand gips iso gips 125mm 25-75-25_ags
Name (Basic Wall:NLRS_22_WA_ms-wand gips iso gips 125mm 25-75-25_ags:...) | In | Height (mm) | Length (mm) | GrossFootprintArea (m2) | GrossVolume (m3) | GrossSideArea (m2) | NetSideArea (m2) | NetVolume (m3)
6227912 | 02 2e verdieping | 3200 | 6011.65 | 0.716362 | 2.40466 | 19.2373 | 18.9348 | 2.25455
6244194 | 01 1e verdieping | 4550 | 3174.94 | 0.37932 | 1.80575 | 14.446 | 12.2326 | 1.44923
6424319 | 01 1e verdieping | 4500 | 2209.15 | 0.276143 | 0.740832 | 5.92666 | 5.92666 | 0.740832
6424405 | 01 1e verdieping | 4500 | 1287.85 | 0.160981 | 0.724416 | 5.79533 | 5.79533 | 0.724416

# IfcWallStandardCase: Basic Wall:NLRS_22_WA_ms-wand mdf gips iso 100mm 25-75_ags (8)
Type - PredefinedType: STANDARD; Material: NLRS_MDF 12.5 mm, NLRS_gipsplaat 12.5 mm, NLRS_aluminium C-profielen met isolatie 75 mm
Type - Pset_ElementShading - Roughness: 304.8 mm
Type - Pset_ProductRequirements - Category: Walls
Type - Pset_ReinforcementBarPitchOfWall - Description: Gipsmontagewand 100 mm geisoleerd dubbele plaat enkelzijdig
Type - Pset_WallCommon - IsExternal: no
Classification: 22.13 binnenwanden; niet constructief, systeemwanden; vast (Uniformat)
BaseQuantities - Width: 100 mm
Pset_QuantityTakeOff - Reference: Basic Wall:NLRS_22_WA_ms-wand mdf gips iso 100mm 25-75_ags; sets with these values: 2
Pset_WallCommon - ExtendToStructure: no; LoadBearing: no; Reference: Basic Wall:NLRS_22_WA_ms-wand mdf gips iso 100mm 25-75_ags
Name (Basic Wall:NLRS_22_WA_ms-wand mdf gips iso 100mm 25-75_ags:...) | In | Height (mm) | Length (mm) | GrossFootprintArea (m2) | GrossVolume (m3) | GrossSideArea (m2) = NetSideArea (m2) | NetVolume (m3)
6147856 | 01 1e verdieping | 4500 | 806.537 | 0.0719934 | 0.362942 | 3.62942 | 0.32397
6149480 | 01 1e verdieping | 4500 | 806.537 | 0.0719934 | 0.362942 | 3.62942 | 0.32397
6225279 | 02 2e verdieping | 3200 | 1606.54 | 0.151993 | 0.514092 | 5.14092 | 0.486379
6225747 | 02 2e verdieping | 3200 | 1606.54 | 0.151993 | 0.514092 | 5.14092 | 0.486379
6395691 | 01 1e verdieping | 4500 | 500 | 0.05 | 0.225 | 2.25 | 0.225
6395825 | 01 1e verdieping | 4500 | 947.22 | 0.0860618 | 0.426249 | 4.26249 | 0.387278
6396386 | 01 1e verdieping | 4500 | 500 | 0.05 | 0.225 | 2.25 | 0.225
6396387 | 01 1e verdieping | 4500 | 947.22 | 0.0860618 | 0.426249 | 4.26249 | 0.387278

# IfcWallStandardCase: Basic Wall:NLRS_22_WA_ms-wand mdf gips iso 125mm 25-100_ags (9)
In: 01 1e verdieping
Type - PredefinedType: STANDARD; Material: NLRS_MDF 12.5 mm, NLRS_gipsplaat 12.5 mm, NLRS_aluminium C-profielen met isolatie 100 mm
Type - Pset_ElementShading - Roughness: 304.8 mm
Type - Pset_ProductRequirements - Category: Walls
Type - Pset_WallCommon - IsExternal: no
Classification: 22.13 binnenwanden; niet constructief, systeemwanden; vast (Uniformat)
BaseQuantities - Height: 2705 mm; Width: 125 mm
Pset_QuantityTakeOff - Reference: Basic Wall:NLRS_22_WA_ms-wand mdf gips iso 125mm 25-100_ags; sets with these values: 2
Pset_WallCommon - ExtendToStructure: no; LoadBearing: no; Reference: Basic Wall:NLRS_22_WA_ms-wand mdf gips iso 125mm 25-100_ags
Name (Basic Wall:NLRS_22_WA_ms-wand mdf gips iso 125mm 25-100_ags:...) | Length (mm) | GrossFootprintArea (m2) | GrossVolume (m3) | GrossSideArea (m2) = NetSideArea (m2) | NetVolume (m3)
6222410 | 714.49 | 0.0893113 | 0.241587 | 1.9327 | 0.241587
6222706 | 596.106 | 0.0745133 | 0.201558 | 1.61247 | 0.201558
6256860 | 1108.19 | 0.116046 | 0.32593 | 2.60744 | 0.32593
6258122 | 1100 | 0.1375 | 0.371937 | 2.9755 | 0.371937
6258492 | 1100 | 0.1375 | 0.371937 | 2.9755 | 0.371937
6258726 | 1100 | 0.1375 | 0.371938 | 2.9755 | 0.371937
6259493 | 1100 | 0.1375 | 0.371937 | 2.9755 | 0.371937
6259764 | 1100 | 0.1375 | 0.371937 | 2.9755 | 0.371937
6260049 | 1100 | 0.1375 | 0.371938 | 2.9755 | 0.371937

# IfcWallStandardCase: Basic Wall:NLRS_22_WA_ms-wand mdf gips iso gips gips 125mm 25-75-25_ags (8)
Type - PredefinedType: STANDARD; Material: NLRS_MDF 12.5 mm, NLRS_gipsplaat 12.5 mm, NLRS_aluminium C-profielen met isolatie 75 mm, NLRS_gipsplaat 12.5 mm, NLRS_gipsplaat 12.5 mm
Type - Pset_ElementShading - Roughness: 304.8 mm
Type - Pset_ProductRequirements - Category: Walls
Type - Pset_ReinforcementBarPitchOfWall - Description: Gipsmontagewand 125 mm geisoleerd dubbele plaat tweezijdig
Type - Pset_WallCommon - IsExternal: no
Classification: 22.13 binnenwanden; niet constructief, systeemwanden; vast (Uniformat)
BaseQuantities - Width: 125 mm
Pset_QuantityTakeOff - Reference: Basic Wall:NLRS_22_WA_ms-wand mdf gips iso gips gips 125mm 25-75-25_ags; sets with these values: 2
Pset_WallCommon - ExtendToStructure: no; LoadBearing: no; Reference: Basic Wall:NLRS_22_WA_ms-wand mdf gips iso gips gips 125mm 25-75-25_ags
Name (Basic Wall:NLRS_22_WA_ms-wand mdf gips iso gips gips 125mm 25-75-25_ags:...) | In | Height (mm) | Length (mm) | GrossFootprintArea (m2) | GrossVolume (m3) | GrossSideArea (m2) = NetSideArea (m2) | NetVolume (m3)
6147855 | 01 1e verdieping | 4500 | 1386.22 | 0.167601 | 0.779751 | 6.23801 | 0.754202
6147858 | 01 1e verdieping | 4500 | 1755.92 | 0.213812 | 0.656778 | 5.25423 | 0.63123
6149479 | 01 1e verdieping | 4500 | 1438.87 | 0.174181 | 0.809363 | 6.47491 | 0.783815
6149482 | 01 1e verdieping | 4500 | 1755.92 | 0.213812 | 0.705603 | 5.64483 | 0.680055
6225278 | 02 2e verdieping | 3200 | 1386.16 | 0.167593 | 0.554464 | 4.43571 | 0.536296
6225281 | 02 2e verdieping | 3200 | 1755.92 | 0.213812 | 0.420267 | 3.36213 | 0.402099
6225746 | 02 2e verdieping | 3200 | 1438.87 | 0.174181 | 0.575547 | 4.60438 | 0.557379
6225749 | 02 2e verdieping | 3200 | 1755.92 | 0.213812 | 0.420267 | 3.36213 | 0.402099

# IfcWallStandardCase: Basic Wall:NLRS_22_WA_ms-wand mdfi gips iso 200mm 25-175_ags (11)
In: 02 2e verdieping
Type - PredefinedType: STANDARD; Material: NLRS_MDF 12.5 mm, NLRS_gipsplaat 12.5 mm, NLRS_aluminium C-profielen met isolatie 175 mm
Type - Pset_ElementShading - Roughness: 304.8 mm
Type - Pset_ProductRequirements - Category: Walls
Type - Pset_ReinforcementBarPitchOfWall - Description: Gipsmontagewand 200 mm geisoleerd dubbele plaat enkelzijdig
Type - Pset_WallCommon - IsExternal: no
Classification: 22.13 binnenwanden; niet constructief, systeemwanden; vast (Uniformat)
BaseQuantities - Height: 2200 mm; Width: 200 mm
Pset_QuantityTakeOff - Reference: Basic Wall:NLRS_22_WA_ms-wand mdfi gips iso 200mm 25-175_ags; sets with these values: 2
Pset_WallCommon - ExtendToStructure: no; LoadBearing: no; Reference: Basic Wall:NLRS_22_WA_ms-wand mdfi gips iso 200mm 25-175_ags
Name (Basic Wall:NLRS_22_WA_ms-wand mdfi gips iso 200mm 25-175_ags:...) | Length (mm) | GrossFootprintArea (m2) | GrossVolume (m3) | GrossSideArea (m2) | NetSideArea (m2) | NetVolume (m3)
6283697 | 1225.21 | 0.200121 | 0.539091 | 2.69546 | 2.69546 | 0.440265
6283699 | 1100 | 0.22 | 0.484 | 2.42 | 2.42 | 0.484
6283701 | 1100 | 0.22 | 0.484 | 2.42 | 2.42 | 0.484
6283702 | 1100 | 0.22 | 0.484 | 2.42 | 2.42 | 0.484
6283704 | 1100 | 0.22 | 0.484 | 2.42 | 2.42 | 0.484
6283706 | 1225.21 | 0.200121 | 0.539091 | 2.69546 | 2.69546 | 0.440265
6284880 | 714.484 | 0.142897 | 0.314373 | 1.57186 | 1.57186 | 0.314373
6285388 | 1100 | 0.22 | 0.484 | 2.42 | 2.1175 | 0.4235
6285710 | 1248.52 | 0.204784 | 0.54935 | 2.74675 | 2.74675 | 0.450524
6285887 | 1378.11 | 0.230701 | 0.606368 | 3.03184 | 3.03184 | 0.507543
6286077 | 596.093 | 0.119219 | 0.262281 | 1.31141 | 1.31141 | 0.262281

# IfcWallStandardCase: Basic Wall:NLRS_41_WA_multiplex op regelwerk 65mm 15-50mm, Basic Wall:NLRS_41_WA_multiplex op regelwerk 65mm 15-50mm:6252133
In: 01 1e verdieping
Type - PredefinedType: STANDARD; Material: NLRS_multiplex 18 mm, NLRS_houten regelwerk 50 mm
Type - Pset_ElementShading - Roughness: 304.8 mm
Type - Pset_ProductRequirements - Category: Walls
Type - Pset_ReinforcementBarPitchOfWall - Description: Multiplec 15mm op regelwerk 50mm
Type - Pset_WallCommon - IsExternal: yes; ThermalTransmittance: 5.88889 kg/K/s3
Classification: 41.12 buitenwandafwerkingen; bekledingen (Uniformat)
BaseQuantities - Height: 4500 mm; Length: 724.033 mm; Width: 68 mm; GrossFootprintArea: 0.0482049 m2; GrossVolume: 0.221554 m3; GrossSideArea: 3.25815 m2; NetSideArea: 3.25815 m2; NetVolume: 0.216922 m3
Pset_QuantityTakeOff - Reference: Basic Wall:NLRS_41_WA_multiplex op regelwerk 65mm 15-50mm; sets with these values: 2
Pset_WallCommon - ExtendToStructure: no; LoadBearing: no; Reference: Basic Wall:NLRS_41_WA_multiplex op regelwerk 65mm 15-50mm

# IfcWallStandardCase: Basic Wall:NLRS_42_WA_multiplex 13mm_ags (6)
Type - PredefinedType: STANDARD; Material: NLRS_multiplex 13 mm
Type - Pset_ElementShading - Roughness: 304.8 mm
Type - Pset_ProductRequirements - Category: Walls
Type - Pset_ReinforcementBarPitchOfWall - Description: Multiplex 13mm
Type - Pset_WallCommon - IsExternal: no; ThermalTransmittance: 8.15385 kg/K/s3
Classification: 42.12 binnenwandafwerkingen; bekledingen (Uniformat)
BaseQuantities - Width: 13 mm
Pset_QuantityTakeOff - Reference: Basic Wall:NLRS_42_WA_multiplex 13mm_ags; sets with these values: 2
Pset_WallCommon - ExtendToStructure: no; LoadBearing: no; Reference: Basic Wall:NLRS_42_WA_multiplex 13mm_ags
Name (Basic Wall:NLRS_42_WA_multiplex 13mm_ags:...) | In | Height (mm) | Length (mm) | GrossFootprintArea (m2) | GrossVolume (m3) | GrossSideArea (m2) = NetSideArea (m2) | NetVolume (m3)
6155876 | 01 1e verdieping | 4500 | 2048.01 | 0.0265865 | 0.119809 | 9.21606 | 0.119639
6293418 | 01 1e verdieping | 4500 | 2036.33 | 0.026434 | 0.119125 | 9.16348 | 0.118953
6332473 | 01 1e verdieping | 4800 | 1274.9 | 0.0165737 | 0.0795537 | 6.11952 | 0.0795537
6332473 | 02 2e verdieping | 3500 | 1274.9 | 0.0165737 | 0.0580079 | 4.46215 | 0.0580079
6338225 | 01 1e verdieping | 4800 | 1295.03 | 0.0168354 | 0.0808101 | 6.21616 | 0.0808101
6338225 | 02 2e verdieping | 3500 | 1295.03 | 0.0168354 | 0.0589241 | 4.53262 | 0.0589241

# IfcWallStandardCase: Basic Wall:NLRS_42_WA_multiplex 18mm_ags (18)
Type - PredefinedType: STANDARD; Material: NLRS_multiplex 18 mm
Type - Pset_ElementShading - Roughness: 304.8 mm
Type - Pset_ProductRequirements - Category: Walls
Type - Pset_ReinforcementBarPitchOfWall - Description: Multiplex 18mm
Type - Pset_WallCommon - IsExternal: no; ThermalTransmittance: 5.88889 kg/K/s3
Classification: 42.12 binnenwandafwerkingen; bekledingen (Uniformat)
BaseQuantities - Width: 18 mm
Pset_QuantityTakeOff - Reference: Basic Wall:NLRS_42_WA_multiplex 18mm_ags; sets with these values: 2
Pset_WallCommon - ExtendToStructure: no; LoadBearing: no; Reference: Basic Wall:NLRS_42_WA_multiplex 18mm_ags
Name (Basic Wall:NLRS_42_WA_multiplex 18mm_ags:...) | In | Height (mm) | Length (mm) | GrossFootprintArea (m2) | GrossVolume (m3) | GrossSideArea (m2) = NetSideArea (m2) | NetVolume (m3)
6153684 | 01 1e verdieping | 4500 | 1280.56 | 0.0229779 | 0.103725 | 5.76251 | 0.103401
6155287 | 01 1e verdieping | 4500 | 280 | 0.00504 | 0.02268 | 1.26 | 0.02268
6286624 | 01 1e verdieping | 4500 | 540 | 0.00972 | 0.04374 | 2.43 | 0.04374
6287880 | 01 1e verdieping | 4800 | 131.016 | 0.00235829 | 0.0113198 | 0.628878 | 0.0113198
6287880 | 02 2e verdieping | 3500 | 131.016 | 0.00235829 | 0.00825402 | 0.458557 | 0.00825402
6288042 | 02 2e verdieping | 2170 | 100.14 | 0.00180252 | 0.00391147 | 0.217304 | 0.00391147
6288726 | 02 2e verdieping | 2107 | 109.14 | 0.00196452 | 0.00413924 | 0.229958 | 0.00413924
6293415 | 01 1e verdieping | 4500 | 660.997 | 0.011898 | 0.0535408 | 2.97449 | 0.0535408
6293417 | 01 1e verdieping | 4500 | 280 | 0.00504 | 0.02268 | 1.26 | 0.02268
6293419 | 01 1e verdieping | 4500 | 1148.49 | 0.0205996 | 0.0930279 | 5.16822 | 0.0926981
6293852 | 02 2e verdieping | 2170 | 92.7399 | 0.00166932 | 0.00362242 | 0.201246 | 0.00362242
6332450 | 01 1e verdieping | 4800 | 1274.9 | 0.0229482 | 0.110151 | 6.11952 | 0.110151
6332450 | 02 2e verdieping | 3500 | 1274.9 | 0.0229482 | 0.0803187 | 4.46215 | 0.0803187
6337996 | 01 1e verdieping | 4800 | 130.5 | 0.002349 | 0.0112752 | 0.6264 | 0.0112752
6337996 | 02 2e verdieping | 3500 | 130.5 | 0.002349 | 0.0082215 | 0.45675 | 0.0082215
6338150 | 01 1e verdieping | 4800 | 1295.03 | 0.0233106 | 0.111891 | 6.21616 | 0.111891
6338150 | 02 2e verdieping | 3500 | 1295.03 | 0.0233106 | 0.0815872 | 4.53262 | 0.0815872
6338974 | 02 2e verdieping | 2170 | 99.5 | 0.001791 | 0.00388647 | 0.215915 | 0.00388647

# IfcWallStandardCase: Basic Wall:NLRS_42_WA_multiplex 25mm_ags (3)
In: 01 1e verdieping
Type - PredefinedType: STANDARD; Material: 36_APX_multiplex 25 mm
Type - Pset_ElementShading - Roughness: 304.8 mm
Type - Pset_ProductRequirements - Category: Walls
Type - Pset_ReinforcementBarPitchOfWall - Description: Multiplex 25mm
Type - Pset_WallCommon - IsExternal: no
Classification: 42.12 binnenwandafwerkingen; bekledingen (Uniformat)
BaseQuantities - Height: 620 mm; Width: 25 mm
Pset_QuantityTakeOff - Reference: Basic Wall:NLRS_42_WA_multiplex 25mm_ags; sets with these values: 2
Pset_WallCommon - ExtendToStructure: no; LoadBearing: no; Reference: Basic Wall:NLRS_42_WA_multiplex 25mm_ags
Name (Basic Wall:NLRS_42_WA_multiplex 25mm_ags:...) | Length (mm) | GrossFootprintArea (m2) | GrossVolume (m3) | GrossSideArea (m2) = NetSideArea (m2) | NetVolume (m3)
6347918 | 7154.87 | 0.17817 | 0.110901 | 4.43602 | 0.110465
6348051 | 5248.47 | 0.129808 | 0.0813513 | 3.25405 | 0.080481
6348117 | 7093.41 | 0.176633 | 0.109948 | 4.39792 | 0.109513
